VERSION 5.8 ;
BUSBITCHARS "[]" ;
DIVIDERCHAR "/" ;
UNITS
    DATABASE MICRONS 1000 ;
END UNITS

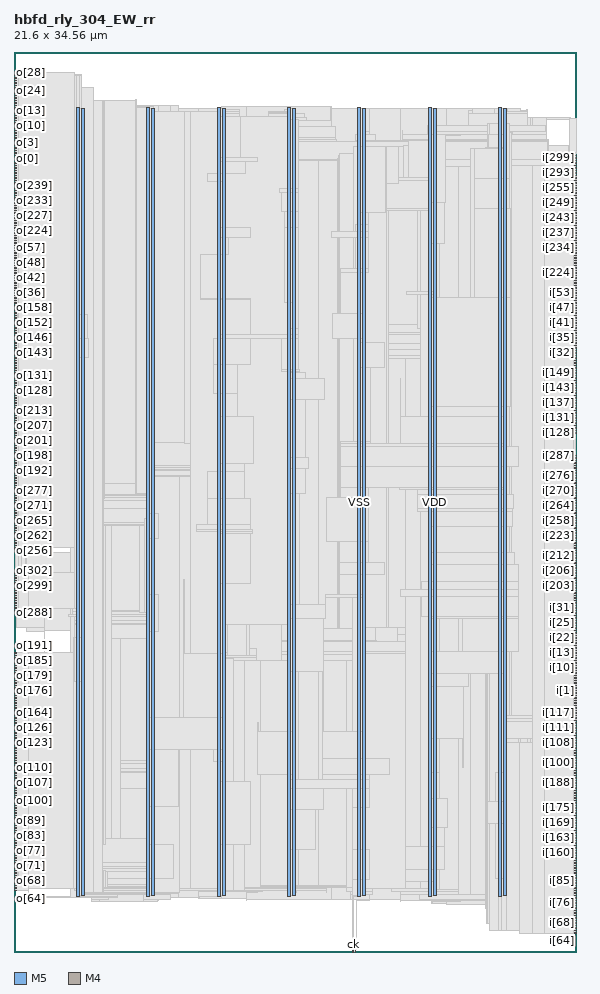
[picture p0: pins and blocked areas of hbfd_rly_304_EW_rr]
MACRO hbfd_rly_304_EW_rr
  FOREIGN hbfd_rly_304_EW_rr 0 0 ;
  CLASS BLOCK ;
  SIZE 21.6 BY 34.56 ;
  PIN ck
    DIRECTION INPUT ;
    USE SIGNAL ;
    PORT
      LAYER M5 ;
        RECT  13.008 0 13.032 0.084 ;
    END
  END ck
  PIN i[0]
    DIRECTION INPUT ;
    USE SIGNAL ;
    PORT
      LAYER M4 ;
        RECT  21.516 9.936 21.6 9.96 ;
    END
  END i[0]
  PIN i[100]
    DIRECTION INPUT ;
    USE SIGNAL ;
    PORT
      LAYER M4 ;
        RECT  21.516 7.248 21.6 7.272 ;
    END
  END i[100]
  PIN i[101]
    DIRECTION INPUT ;
    USE SIGNAL ;
    PORT
      LAYER M4 ;
        RECT  21.516 7.344 21.6 7.368 ;
    END
  END i[101]
  PIN i[102]
    DIRECTION INPUT ;
    USE SIGNAL ;
    PORT
      LAYER M4 ;
        RECT  21.516 7.44 21.6 7.464 ;
    END
  END i[102]
  PIN i[103]
    DIRECTION INPUT ;
    USE SIGNAL ;
    PORT
      LAYER M4 ;
        RECT  21.516 7.536 21.6 7.56 ;
    END
  END i[103]
  PIN i[104]
    DIRECTION INPUT ;
    USE SIGNAL ;
    PORT
      LAYER M4 ;
        RECT  21.516 7.632 21.6 7.656 ;
    END
  END i[104]
  PIN i[105]
    DIRECTION INPUT ;
    USE SIGNAL ;
    PORT
      LAYER M4 ;
        RECT  21.516 7.728 21.6 7.752 ;
    END
  END i[105]
  PIN i[106]
    DIRECTION INPUT ;
    USE SIGNAL ;
    PORT
      LAYER M4 ;
        RECT  21.516 7.824 21.6 7.848 ;
    END
  END i[106]
  PIN i[107]
    DIRECTION INPUT ;
    USE SIGNAL ;
    PORT
      LAYER M4 ;
        RECT  21.516 7.92 21.6 7.944 ;
    END
  END i[107]
  PIN i[108]
    DIRECTION INPUT ;
    USE SIGNAL ;
    PORT
      LAYER M4 ;
        RECT  21.516 8.016 21.6 8.04 ;
    END
  END i[108]
  PIN i[109]
    DIRECTION INPUT ;
    USE SIGNAL ;
    PORT
      LAYER M4 ;
        RECT  21.516 8.112 21.6 8.136 ;
    END
  END i[109]
  PIN i[10]
    DIRECTION INPUT ;
    USE SIGNAL ;
    PORT
      LAYER M4 ;
        RECT  21.516 10.896 21.6 10.92 ;
    END
  END i[10]
  PIN i[110]
    DIRECTION INPUT ;
    USE SIGNAL ;
    PORT
      LAYER M4 ;
        RECT  21.516 8.208 21.6 8.232 ;
    END
  END i[110]
  PIN i[111]
    DIRECTION INPUT ;
    USE SIGNAL ;
    PORT
      LAYER M4 ;
        RECT  21.516 8.304 21.6 8.328 ;
    END
  END i[111]
  PIN i[112]
    DIRECTION INPUT ;
    USE SIGNAL ;
    PORT
      LAYER M4 ;
        RECT  21.516 8.4 21.6 8.424 ;
    END
  END i[112]
  PIN i[113]
    DIRECTION INPUT ;
    USE SIGNAL ;
    PORT
      LAYER M4 ;
        RECT  21.516 8.496 21.6 8.52 ;
    END
  END i[113]
  PIN i[114]
    DIRECTION INPUT ;
    USE SIGNAL ;
    PORT
      LAYER M4 ;
        RECT  21.516 8.592 21.6 8.616 ;
    END
  END i[114]
  PIN i[115]
    DIRECTION INPUT ;
    USE SIGNAL ;
    PORT
      LAYER M4 ;
        RECT  21.516 8.688 21.6 8.712 ;
    END
  END i[115]
  PIN i[116]
    DIRECTION INPUT ;
    USE SIGNAL ;
    PORT
      LAYER M4 ;
        RECT  21.516 8.784 21.6 8.808 ;
    END
  END i[116]
  PIN i[117]
    DIRECTION INPUT ;
    USE SIGNAL ;
    PORT
      LAYER M4 ;
        RECT  21.516 8.88 21.6 8.904 ;
    END
  END i[117]
  PIN i[118]
    DIRECTION INPUT ;
    USE SIGNAL ;
    PORT
      LAYER M4 ;
        RECT  21.516 8.976 21.6 9 ;
    END
  END i[118]
  PIN i[119]
    DIRECTION INPUT ;
    USE SIGNAL ;
    PORT
      LAYER M4 ;
        RECT  21.516 9.072 21.6 9.096 ;
    END
  END i[119]
  PIN i[11]
    DIRECTION INPUT ;
    USE SIGNAL ;
    PORT
      LAYER M4 ;
        RECT  21.516 10.992 21.6 11.016 ;
    END
  END i[11]
  PIN i[120]
    DIRECTION INPUT ;
    USE SIGNAL ;
    PORT
      LAYER M4 ;
        RECT  21.516 9.168 21.6 9.192 ;
    END
  END i[120]
  PIN i[121]
    DIRECTION INPUT ;
    USE SIGNAL ;
    PORT
      LAYER M4 ;
        RECT  21.516 9.264 21.6 9.288 ;
    END
  END i[121]
  PIN i[122]
    DIRECTION INPUT ;
    USE SIGNAL ;
    PORT
      LAYER M4 ;
        RECT  21.516 9.36 21.6 9.384 ;
    END
  END i[122]
  PIN i[123]
    DIRECTION INPUT ;
    USE SIGNAL ;
    PORT
      LAYER M4 ;
        RECT  21.516 9.456 21.6 9.48 ;
    END
  END i[123]
  PIN i[124]
    DIRECTION INPUT ;
    USE SIGNAL ;
    PORT
      LAYER M4 ;
        RECT  21.516 9.552 21.6 9.576 ;
    END
  END i[124]
  PIN i[125]
    DIRECTION INPUT ;
    USE SIGNAL ;
    PORT
      LAYER M4 ;
        RECT  21.516 9.648 21.6 9.672 ;
    END
  END i[125]
  PIN i[126]
    DIRECTION INPUT ;
    USE SIGNAL ;
    PORT
      LAYER M4 ;
        RECT  21.516 9.744 21.6 9.768 ;
    END
  END i[126]
  PIN i[127]
    DIRECTION INPUT ;
    USE SIGNAL ;
    PORT
      LAYER M4 ;
        RECT  21.516 9.84 21.6 9.864 ;
    END
  END i[127]
  PIN i[128]
    DIRECTION INPUT ;
    USE SIGNAL ;
    PORT
      LAYER M4 ;
        RECT  21.516 19.92 21.6 19.944 ;
    END
  END i[128]
  PIN i[129]
    DIRECTION INPUT ;
    USE SIGNAL ;
    PORT
      LAYER M4 ;
        RECT  21.516 20.016 21.6 20.04 ;
    END
  END i[129]
  PIN i[12]
    DIRECTION INPUT ;
    USE SIGNAL ;
    PORT
      LAYER M4 ;
        RECT  21.516 11.088 21.6 11.112 ;
    END
  END i[12]
  PIN i[130]
    DIRECTION INPUT ;
    USE SIGNAL ;
    PORT
      LAYER M4 ;
        RECT  21.516 20.112 21.6 20.136 ;
    END
  END i[130]
  PIN i[131]
    DIRECTION INPUT ;
    USE SIGNAL ;
    PORT
      LAYER M4 ;
        RECT  21.516 20.208 21.6 20.232 ;
    END
  END i[131]
  PIN i[132]
    DIRECTION INPUT ;
    USE SIGNAL ;
    PORT
      LAYER M4 ;
        RECT  21.516 20.304 21.6 20.328 ;
    END
  END i[132]
  PIN i[133]
    DIRECTION INPUT ;
    USE SIGNAL ;
    PORT
      LAYER M4 ;
        RECT  21.516 20.4 21.6 20.424 ;
    END
  END i[133]
  PIN i[134]
    DIRECTION INPUT ;
    USE SIGNAL ;
    PORT
      LAYER M4 ;
        RECT  21.516 20.496 21.6 20.52 ;
    END
  END i[134]
  PIN i[135]
    DIRECTION INPUT ;
    USE SIGNAL ;
    PORT
      LAYER M4 ;
        RECT  21.516 20.592 21.6 20.616 ;
    END
  END i[135]
  PIN i[136]
    DIRECTION INPUT ;
    USE SIGNAL ;
    PORT
      LAYER M4 ;
        RECT  21.516 20.688 21.6 20.712 ;
    END
  END i[136]
  PIN i[137]
    DIRECTION INPUT ;
    USE SIGNAL ;
    PORT
      LAYER M4 ;
        RECT  21.516 20.784 21.6 20.808 ;
    END
  END i[137]
  PIN i[138]
    DIRECTION INPUT ;
    USE SIGNAL ;
    PORT
      LAYER M4 ;
        RECT  21.516 20.88 21.6 20.904 ;
    END
  END i[138]
  PIN i[139]
    DIRECTION INPUT ;
    USE SIGNAL ;
    PORT
      LAYER M4 ;
        RECT  21.516 20.976 21.6 21 ;
    END
  END i[139]
  PIN i[13]
    DIRECTION INPUT ;
    USE SIGNAL ;
    PORT
      LAYER M4 ;
        RECT  21.516 11.184 21.6 11.208 ;
    END
  END i[13]
  PIN i[140]
    DIRECTION INPUT ;
    USE SIGNAL ;
    PORT
      LAYER M4 ;
        RECT  21.516 21.072 21.6 21.096 ;
    END
  END i[140]
  PIN i[141]
    DIRECTION INPUT ;
    USE SIGNAL ;
    PORT
      LAYER M4 ;
        RECT  21.516 21.168 21.6 21.192 ;
    END
  END i[141]
  PIN i[142]
    DIRECTION INPUT ;
    USE SIGNAL ;
    PORT
      LAYER M4 ;
        RECT  21.516 21.264 21.6 21.288 ;
    END
  END i[142]
  PIN i[143]
    DIRECTION INPUT ;
    USE SIGNAL ;
    PORT
      LAYER M4 ;
        RECT  21.516 21.36 21.6 21.384 ;
    END
  END i[143]
  PIN i[144]
    DIRECTION INPUT ;
    USE SIGNAL ;
    PORT
      LAYER M4 ;
        RECT  21.516 21.456 21.6 21.48 ;
    END
  END i[144]
  PIN i[145]
    DIRECTION INPUT ;
    USE SIGNAL ;
    PORT
      LAYER M4 ;
        RECT  21.516 21.552 21.6 21.576 ;
    END
  END i[145]
  PIN i[146]
    DIRECTION INPUT ;
    USE SIGNAL ;
    PORT
      LAYER M4 ;
        RECT  21.516 21.648 21.6 21.672 ;
    END
  END i[146]
  PIN i[147]
    DIRECTION INPUT ;
    USE SIGNAL ;
    PORT
      LAYER M4 ;
        RECT  21.516 21.744 21.6 21.768 ;
    END
  END i[147]
  PIN i[148]
    DIRECTION INPUT ;
    USE SIGNAL ;
    PORT
      LAYER M4 ;
        RECT  21.516 21.84 21.6 21.864 ;
    END
  END i[148]
  PIN i[149]
    DIRECTION INPUT ;
    USE SIGNAL ;
    PORT
      LAYER M4 ;
        RECT  21.516 21.936 21.6 21.96 ;
    END
  END i[149]
  PIN i[14]
    DIRECTION INPUT ;
    USE SIGNAL ;
    PORT
      LAYER M4 ;
        RECT  21.516 11.28 21.6 11.304 ;
    END
  END i[14]
  PIN i[150]
    DIRECTION INPUT ;
    USE SIGNAL ;
    PORT
      LAYER M4 ;
        RECT  21.516 22.032 21.6 22.056 ;
    END
  END i[150]
  PIN i[151]
    DIRECTION INPUT ;
    USE SIGNAL ;
    PORT
      LAYER M4 ;
        RECT  21.516 22.128 21.6 22.152 ;
    END
  END i[151]
  PIN i[152]
    DIRECTION INPUT ;
    USE SIGNAL ;
    PORT
      LAYER M4 ;
        RECT  21.516 22.224 21.6 22.248 ;
    END
  END i[152]
  PIN i[153]
    DIRECTION INPUT ;
    USE SIGNAL ;
    PORT
      LAYER M4 ;
        RECT  21.516 22.32 21.6 22.344 ;
    END
  END i[153]
  PIN i[154]
    DIRECTION INPUT ;
    USE SIGNAL ;
    PORT
      LAYER M4 ;
        RECT  21.516 22.416 21.6 22.44 ;
    END
  END i[154]
  PIN i[155]
    DIRECTION INPUT ;
    USE SIGNAL ;
    PORT
      LAYER M4 ;
        RECT  21.516 22.512 21.6 22.536 ;
    END
  END i[155]
  PIN i[156]
    DIRECTION INPUT ;
    USE SIGNAL ;
    PORT
      LAYER M4 ;
        RECT  21.516 22.608 21.6 22.632 ;
    END
  END i[156]
  PIN i[157]
    DIRECTION INPUT ;
    USE SIGNAL ;
    PORT
      LAYER M4 ;
        RECT  21.516 22.704 21.6 22.728 ;
    END
  END i[157]
  PIN i[158]
    DIRECTION INPUT ;
    USE SIGNAL ;
    PORT
      LAYER M4 ;
        RECT  21.516 22.8 21.6 22.824 ;
    END
  END i[158]
  PIN i[159]
    DIRECTION INPUT ;
    USE SIGNAL ;
    PORT
      LAYER M4 ;
        RECT  21.516 22.896 21.6 22.92 ;
    END
  END i[159]
  PIN i[15]
    DIRECTION INPUT ;
    USE SIGNAL ;
    PORT
      LAYER M4 ;
        RECT  21.516 11.376 21.6 11.4 ;
    END
  END i[15]
  PIN i[160]
    DIRECTION INPUT ;
    USE SIGNAL ;
    PORT
      LAYER M4 ;
        RECT  21.516 3.792 21.6 3.816 ;
    END
  END i[160]
  PIN i[161]
    DIRECTION INPUT ;
    USE SIGNAL ;
    PORT
      LAYER M4 ;
        RECT  21.516 3.888 21.6 3.912 ;
    END
  END i[161]
  PIN i[162]
    DIRECTION INPUT ;
    USE SIGNAL ;
    PORT
      LAYER M4 ;
        RECT  21.516 3.984 21.6 4.008 ;
    END
  END i[162]
  PIN i[163]
    DIRECTION INPUT ;
    USE SIGNAL ;
    PORT
      LAYER M4 ;
        RECT  21.516 4.08 21.6 4.104 ;
    END
  END i[163]
  PIN i[164]
    DIRECTION INPUT ;
    USE SIGNAL ;
    PORT
      LAYER M4 ;
        RECT  21.516 4.176 21.6 4.2 ;
    END
  END i[164]
  PIN i[165]
    DIRECTION INPUT ;
    USE SIGNAL ;
    PORT
      LAYER M4 ;
        RECT  21.516 4.272 21.6 4.296 ;
    END
  END i[165]
  PIN i[166]
    DIRECTION INPUT ;
    USE SIGNAL ;
    PORT
      LAYER M4 ;
        RECT  21.516 4.368 21.6 4.392 ;
    END
  END i[166]
  PIN i[167]
    DIRECTION INPUT ;
    USE SIGNAL ;
    PORT
      LAYER M4 ;
        RECT  21.516 4.464 21.6 4.488 ;
    END
  END i[167]
  PIN i[168]
    DIRECTION INPUT ;
    USE SIGNAL ;
    PORT
      LAYER M4 ;
        RECT  21.516 4.56 21.6 4.584 ;
    END
  END i[168]
  PIN i[169]
    DIRECTION INPUT ;
    USE SIGNAL ;
    PORT
      LAYER M4 ;
        RECT  21.516 4.656 21.6 4.68 ;
    END
  END i[169]
  PIN i[16]
    DIRECTION INPUT ;
    USE SIGNAL ;
    PORT
      LAYER M4 ;
        RECT  21.516 11.472 21.6 11.496 ;
    END
  END i[16]
  PIN i[170]
    DIRECTION INPUT ;
    USE SIGNAL ;
    PORT
      LAYER M4 ;
        RECT  21.516 4.752 21.6 4.776 ;
    END
  END i[170]
  PIN i[171]
    DIRECTION INPUT ;
    USE SIGNAL ;
    PORT
      LAYER M4 ;
        RECT  21.516 4.848 21.6 4.872 ;
    END
  END i[171]
  PIN i[172]
    DIRECTION INPUT ;
    USE SIGNAL ;
    PORT
      LAYER M4 ;
        RECT  21.516 4.944 21.6 4.968 ;
    END
  END i[172]
  PIN i[173]
    DIRECTION INPUT ;
    USE SIGNAL ;
    PORT
      LAYER M4 ;
        RECT  21.516 5.04 21.6 5.064 ;
    END
  END i[173]
  PIN i[174]
    DIRECTION INPUT ;
    USE SIGNAL ;
    PORT
      LAYER M4 ;
        RECT  21.516 5.136 21.6 5.16 ;
    END
  END i[174]
  PIN i[175]
    DIRECTION INPUT ;
    USE SIGNAL ;
    PORT
      LAYER M4 ;
        RECT  21.516 5.232 21.6 5.256 ;
    END
  END i[175]
  PIN i[176]
    DIRECTION INPUT ;
    USE SIGNAL ;
    PORT
      LAYER M4 ;
        RECT  21.516 5.328 21.6 5.352 ;
    END
  END i[176]
  PIN i[177]
    DIRECTION INPUT ;
    USE SIGNAL ;
    PORT
      LAYER M4 ;
        RECT  21.516 5.424 21.6 5.448 ;
    END
  END i[177]
  PIN i[178]
    DIRECTION INPUT ;
    USE SIGNAL ;
    PORT
      LAYER M4 ;
        RECT  21.516 5.52 21.6 5.544 ;
    END
  END i[178]
  PIN i[179]
    DIRECTION INPUT ;
    USE SIGNAL ;
    PORT
      LAYER M4 ;
        RECT  21.516 5.616 21.6 5.64 ;
    END
  END i[179]
  PIN i[17]
    DIRECTION INPUT ;
    USE SIGNAL ;
    PORT
      LAYER M4 ;
        RECT  21.516 11.568 21.6 11.592 ;
    END
  END i[17]
  PIN i[180]
    DIRECTION INPUT ;
    USE SIGNAL ;
    PORT
      LAYER M4 ;
        RECT  21.516 5.712 21.6 5.736 ;
    END
  END i[180]
  PIN i[181]
    DIRECTION INPUT ;
    USE SIGNAL ;
    PORT
      LAYER M4 ;
        RECT  21.516 5.808 21.6 5.832 ;
    END
  END i[181]
  PIN i[182]
    DIRECTION INPUT ;
    USE SIGNAL ;
    PORT
      LAYER M4 ;
        RECT  21.516 5.904 21.6 5.928 ;
    END
  END i[182]
  PIN i[183]
    DIRECTION INPUT ;
    USE SIGNAL ;
    PORT
      LAYER M4 ;
        RECT  21.516 6 21.6 6.024 ;
    END
  END i[183]
  PIN i[184]
    DIRECTION INPUT ;
    USE SIGNAL ;
    PORT
      LAYER M4 ;
        RECT  21.516 6.096 21.6 6.12 ;
    END
  END i[184]
  PIN i[185]
    DIRECTION INPUT ;
    USE SIGNAL ;
    PORT
      LAYER M4 ;
        RECT  21.516 6.192 21.6 6.216 ;
    END
  END i[185]
  PIN i[186]
    DIRECTION INPUT ;
    USE SIGNAL ;
    PORT
      LAYER M4 ;
        RECT  21.516 6.288 21.6 6.312 ;
    END
  END i[186]
  PIN i[187]
    DIRECTION INPUT ;
    USE SIGNAL ;
    PORT
      LAYER M4 ;
        RECT  21.516 6.384 21.6 6.408 ;
    END
  END i[187]
  PIN i[188]
    DIRECTION INPUT ;
    USE SIGNAL ;
    PORT
      LAYER M4 ;
        RECT  21.516 6.48 21.6 6.504 ;
    END
  END i[188]
  PIN i[189]
    DIRECTION INPUT ;
    USE SIGNAL ;
    PORT
      LAYER M4 ;
        RECT  21.516 6.576 21.6 6.6 ;
    END
  END i[189]
  PIN i[18]
    DIRECTION INPUT ;
    USE SIGNAL ;
    PORT
      LAYER M4 ;
        RECT  21.516 11.664 21.6 11.688 ;
    END
  END i[18]
  PIN i[190]
    DIRECTION INPUT ;
    USE SIGNAL ;
    PORT
      LAYER M4 ;
        RECT  21.516 6.672 21.6 6.696 ;
    END
  END i[190]
  PIN i[191]
    DIRECTION INPUT ;
    USE SIGNAL ;
    PORT
      LAYER M4 ;
        RECT  21.516 6.768 21.6 6.792 ;
    END
  END i[191]
  PIN i[192]
    DIRECTION INPUT ;
    USE SIGNAL ;
    PORT
      LAYER M4 ;
        RECT  21.516 13.008 21.6 13.032 ;
    END
  END i[192]
  PIN i[193]
    DIRECTION INPUT ;
    USE SIGNAL ;
    PORT
      LAYER M4 ;
        RECT  21.516 13.104 21.6 13.128 ;
    END
  END i[193]
  PIN i[194]
    DIRECTION INPUT ;
    USE SIGNAL ;
    PORT
      LAYER M4 ;
        RECT  21.516 13.2 21.6 13.224 ;
    END
  END i[194]
  PIN i[195]
    DIRECTION INPUT ;
    USE SIGNAL ;
    PORT
      LAYER M4 ;
        RECT  21.516 13.296 21.6 13.32 ;
    END
  END i[195]
  PIN i[196]
    DIRECTION INPUT ;
    USE SIGNAL ;
    PORT
      LAYER M4 ;
        RECT  21.516 13.392 21.6 13.416 ;
    END
  END i[196]
  PIN i[197]
    DIRECTION INPUT ;
    USE SIGNAL ;
    PORT
      LAYER M4 ;
        RECT  21.516 13.488 21.6 13.512 ;
    END
  END i[197]
  PIN i[198]
    DIRECTION INPUT ;
    USE SIGNAL ;
    PORT
      LAYER M4 ;
        RECT  21.516 13.584 21.6 13.608 ;
    END
  END i[198]
  PIN i[199]
    DIRECTION INPUT ;
    USE SIGNAL ;
    PORT
      LAYER M4 ;
        RECT  21.516 13.68 21.6 13.704 ;
    END
  END i[199]
  PIN i[19]
    DIRECTION INPUT ;
    USE SIGNAL ;
    PORT
      LAYER M4 ;
        RECT  21.516 11.76 21.6 11.784 ;
    END
  END i[19]
  PIN i[1]
    DIRECTION INPUT ;
    USE SIGNAL ;
    PORT
      LAYER M4 ;
        RECT  21.516 10.032 21.6 10.056 ;
    END
  END i[1]
  PIN i[200]
    DIRECTION INPUT ;
    USE SIGNAL ;
    PORT
      LAYER M4 ;
        RECT  21.516 13.776 21.6 13.8 ;
    END
  END i[200]
  PIN i[201]
    DIRECTION INPUT ;
    USE SIGNAL ;
    PORT
      LAYER M4 ;
        RECT  21.516 13.872 21.6 13.896 ;
    END
  END i[201]
  PIN i[202]
    DIRECTION INPUT ;
    USE SIGNAL ;
    PORT
      LAYER M4 ;
        RECT  21.516 13.968 21.6 13.992 ;
    END
  END i[202]
  PIN i[203]
    DIRECTION INPUT ;
    USE SIGNAL ;
    PORT
      LAYER M4 ;
        RECT  21.516 14.064 21.6 14.088 ;
    END
  END i[203]
  PIN i[204]
    DIRECTION INPUT ;
    USE SIGNAL ;
    PORT
      LAYER M4 ;
        RECT  21.516 14.16 21.6 14.184 ;
    END
  END i[204]
  PIN i[205]
    DIRECTION INPUT ;
    USE SIGNAL ;
    PORT
      LAYER M4 ;
        RECT  21.516 14.256 21.6 14.28 ;
    END
  END i[205]
  PIN i[206]
    DIRECTION INPUT ;
    USE SIGNAL ;
    PORT
      LAYER M4 ;
        RECT  21.516 14.352 21.6 14.376 ;
    END
  END i[206]
  PIN i[207]
    DIRECTION INPUT ;
    USE SIGNAL ;
    PORT
      LAYER M4 ;
        RECT  21.516 14.448 21.6 14.472 ;
    END
  END i[207]
  PIN i[208]
    DIRECTION INPUT ;
    USE SIGNAL ;
    PORT
      LAYER M4 ;
        RECT  21.516 14.544 21.6 14.568 ;
    END
  END i[208]
  PIN i[209]
    DIRECTION INPUT ;
    USE SIGNAL ;
    PORT
      LAYER M4 ;
        RECT  21.516 14.64 21.6 14.664 ;
    END
  END i[209]
  PIN i[20]
    DIRECTION INPUT ;
    USE SIGNAL ;
    PORT
      LAYER M4 ;
        RECT  21.516 11.856 21.6 11.88 ;
    END
  END i[20]
  PIN i[210]
    DIRECTION INPUT ;
    USE SIGNAL ;
    PORT
      LAYER M4 ;
        RECT  21.516 14.736 21.6 14.76 ;
    END
  END i[210]
  PIN i[211]
    DIRECTION INPUT ;
    USE SIGNAL ;
    PORT
      LAYER M4 ;
        RECT  21.516 14.832 21.6 14.856 ;
    END
  END i[211]
  PIN i[212]
    DIRECTION INPUT ;
    USE SIGNAL ;
    PORT
      LAYER M4 ;
        RECT  21.516 14.928 21.6 14.952 ;
    END
  END i[212]
  PIN i[213]
    DIRECTION INPUT ;
    USE SIGNAL ;
    PORT
      LAYER M4 ;
        RECT  21.516 15.024 21.6 15.048 ;
    END
  END i[213]
  PIN i[214]
    DIRECTION INPUT ;
    USE SIGNAL ;
    PORT
      LAYER M4 ;
        RECT  21.516 15.12 21.6 15.144 ;
    END
  END i[214]
  PIN i[215]
    DIRECTION INPUT ;
    USE SIGNAL ;
    PORT
      LAYER M4 ;
        RECT  21.516 15.216 21.6 15.24 ;
    END
  END i[215]
  PIN i[216]
    DIRECTION INPUT ;
    USE SIGNAL ;
    PORT
      LAYER M4 ;
        RECT  21.516 15.312 21.6 15.336 ;
    END
  END i[216]
  PIN i[217]
    DIRECTION INPUT ;
    USE SIGNAL ;
    PORT
      LAYER M4 ;
        RECT  21.516 15.408 21.6 15.432 ;
    END
  END i[217]
  PIN i[218]
    DIRECTION INPUT ;
    USE SIGNAL ;
    PORT
      LAYER M4 ;
        RECT  21.516 15.504 21.6 15.528 ;
    END
  END i[218]
  PIN i[219]
    DIRECTION INPUT ;
    USE SIGNAL ;
    PORT
      LAYER M4 ;
        RECT  21.516 15.6 21.6 15.624 ;
    END
  END i[219]
  PIN i[21]
    DIRECTION INPUT ;
    USE SIGNAL ;
    PORT
      LAYER M4 ;
        RECT  21.516 11.952 21.6 11.976 ;
    END
  END i[21]
  PIN i[220]
    DIRECTION INPUT ;
    USE SIGNAL ;
    PORT
      LAYER M4 ;
        RECT  21.516 15.696 21.6 15.72 ;
    END
  END i[220]
  PIN i[221]
    DIRECTION INPUT ;
    USE SIGNAL ;
    PORT
      LAYER M4 ;
        RECT  21.516 15.792 21.6 15.816 ;
    END
  END i[221]
  PIN i[222]
    DIRECTION INPUT ;
    USE SIGNAL ;
    PORT
      LAYER M4 ;
        RECT  21.516 15.888 21.6 15.912 ;
    END
  END i[222]
  PIN i[223]
    DIRECTION INPUT ;
    USE SIGNAL ;
    PORT
      LAYER M4 ;
        RECT  21.516 15.984 21.6 16.008 ;
    END
  END i[223]
  PIN i[224]
    DIRECTION INPUT ;
    USE SIGNAL ;
    PORT
      LAYER M4 ;
        RECT  21.516 26.064 21.6 26.088 ;
    END
  END i[224]
  PIN i[225]
    DIRECTION INPUT ;
    USE SIGNAL ;
    PORT
      LAYER M4 ;
        RECT  21.516 26.16 21.6 26.184 ;
    END
  END i[225]
  PIN i[226]
    DIRECTION INPUT ;
    USE SIGNAL ;
    PORT
      LAYER M4 ;
        RECT  21.516 26.256 21.6 26.28 ;
    END
  END i[226]
  PIN i[227]
    DIRECTION INPUT ;
    USE SIGNAL ;
    PORT
      LAYER M4 ;
        RECT  21.516 26.352 21.6 26.376 ;
    END
  END i[227]
  PIN i[228]
    DIRECTION INPUT ;
    USE SIGNAL ;
    PORT
      LAYER M4 ;
        RECT  21.516 26.448 21.6 26.472 ;
    END
  END i[228]
  PIN i[229]
    DIRECTION INPUT ;
    USE SIGNAL ;
    PORT
      LAYER M4 ;
        RECT  21.516 26.544 21.6 26.568 ;
    END
  END i[229]
  PIN i[22]
    DIRECTION INPUT ;
    USE SIGNAL ;
    PORT
      LAYER M4 ;
        RECT  21.516 12.048 21.6 12.072 ;
    END
  END i[22]
  PIN i[230]
    DIRECTION INPUT ;
    USE SIGNAL ;
    PORT
      LAYER M4 ;
        RECT  21.516 26.64 21.6 26.664 ;
    END
  END i[230]
  PIN i[231]
    DIRECTION INPUT ;
    USE SIGNAL ;
    PORT
      LAYER M4 ;
        RECT  21.516 26.736 21.6 26.76 ;
    END
  END i[231]
  PIN i[232]
    DIRECTION INPUT ;
    USE SIGNAL ;
    PORT
      LAYER M4 ;
        RECT  21.516 26.832 21.6 26.856 ;
    END
  END i[232]
  PIN i[233]
    DIRECTION INPUT ;
    USE SIGNAL ;
    PORT
      LAYER M4 ;
        RECT  21.516 26.928 21.6 26.952 ;
    END
  END i[233]
  PIN i[234]
    DIRECTION INPUT ;
    USE SIGNAL ;
    PORT
      LAYER M4 ;
        RECT  21.516 27.024 21.6 27.048 ;
    END
  END i[234]
  PIN i[235]
    DIRECTION INPUT ;
    USE SIGNAL ;
    PORT
      LAYER M4 ;
        RECT  21.516 27.12 21.6 27.144 ;
    END
  END i[235]
  PIN i[236]
    DIRECTION INPUT ;
    USE SIGNAL ;
    PORT
      LAYER M4 ;
        RECT  21.516 27.216 21.6 27.24 ;
    END
  END i[236]
  PIN i[237]
    DIRECTION INPUT ;
    USE SIGNAL ;
    PORT
      LAYER M4 ;
        RECT  21.516 27.312 21.6 27.336 ;
    END
  END i[237]
  PIN i[238]
    DIRECTION INPUT ;
    USE SIGNAL ;
    PORT
      LAYER M4 ;
        RECT  21.516 27.408 21.6 27.432 ;
    END
  END i[238]
  PIN i[239]
    DIRECTION INPUT ;
    USE SIGNAL ;
    PORT
      LAYER M4 ;
        RECT  21.516 27.504 21.6 27.528 ;
    END
  END i[239]
  PIN i[23]
    DIRECTION INPUT ;
    USE SIGNAL ;
    PORT
      LAYER M4 ;
        RECT  21.516 12.144 21.6 12.168 ;
    END
  END i[23]
  PIN i[240]
    DIRECTION INPUT ;
    USE SIGNAL ;
    PORT
      LAYER M4 ;
        RECT  21.516 27.6 21.6 27.624 ;
    END
  END i[240]
  PIN i[241]
    DIRECTION INPUT ;
    USE SIGNAL ;
    PORT
      LAYER M4 ;
        RECT  21.516 27.696 21.6 27.72 ;
    END
  END i[241]
  PIN i[242]
    DIRECTION INPUT ;
    USE SIGNAL ;
    PORT
      LAYER M4 ;
        RECT  21.516 27.792 21.6 27.816 ;
    END
  END i[242]
  PIN i[243]
    DIRECTION INPUT ;
    USE SIGNAL ;
    PORT
      LAYER M4 ;
        RECT  21.516 27.888 21.6 27.912 ;
    END
  END i[243]
  PIN i[244]
    DIRECTION INPUT ;
    USE SIGNAL ;
    PORT
      LAYER M4 ;
        RECT  21.516 27.984 21.6 28.008 ;
    END
  END i[244]
  PIN i[245]
    DIRECTION INPUT ;
    USE SIGNAL ;
    PORT
      LAYER M4 ;
        RECT  21.516 28.08 21.6 28.104 ;
    END
  END i[245]
  PIN i[246]
    DIRECTION INPUT ;
    USE SIGNAL ;
    PORT
      LAYER M4 ;
        RECT  21.516 28.176 21.6 28.2 ;
    END
  END i[246]
  PIN i[247]
    DIRECTION INPUT ;
    USE SIGNAL ;
    PORT
      LAYER M4 ;
        RECT  21.516 28.272 21.6 28.296 ;
    END
  END i[247]
  PIN i[248]
    DIRECTION INPUT ;
    USE SIGNAL ;
    PORT
      LAYER M4 ;
        RECT  21.516 28.368 21.6 28.392 ;
    END
  END i[248]
  PIN i[249]
    DIRECTION INPUT ;
    USE SIGNAL ;
    PORT
      LAYER M4 ;
        RECT  21.516 28.464 21.6 28.488 ;
    END
  END i[249]
  PIN i[24]
    DIRECTION INPUT ;
    USE SIGNAL ;
    PORT
      LAYER M4 ;
        RECT  21.516 12.24 21.6 12.264 ;
    END
  END i[24]
  PIN i[250]
    DIRECTION INPUT ;
    USE SIGNAL ;
    PORT
      LAYER M4 ;
        RECT  21.516 28.56 21.6 28.584 ;
    END
  END i[250]
  PIN i[251]
    DIRECTION INPUT ;
    USE SIGNAL ;
    PORT
      LAYER M4 ;
        RECT  21.516 28.656 21.6 28.68 ;
    END
  END i[251]
  PIN i[252]
    DIRECTION INPUT ;
    USE SIGNAL ;
    PORT
      LAYER M4 ;
        RECT  21.516 28.752 21.6 28.776 ;
    END
  END i[252]
  PIN i[253]
    DIRECTION INPUT ;
    USE SIGNAL ;
    PORT
      LAYER M4 ;
        RECT  21.516 28.848 21.6 28.872 ;
    END
  END i[253]
  PIN i[254]
    DIRECTION INPUT ;
    USE SIGNAL ;
    PORT
      LAYER M4 ;
        RECT  21.516 28.944 21.6 28.968 ;
    END
  END i[254]
  PIN i[255]
    DIRECTION INPUT ;
    USE SIGNAL ;
    PORT
      LAYER M4 ;
        RECT  21.516 29.04 21.6 29.064 ;
    END
  END i[255]
  PIN i[256]
    DIRECTION INPUT ;
    USE SIGNAL ;
    PORT
      LAYER M4 ;
        RECT  21.516 16.08 21.6 16.104 ;
    END
  END i[256]
  PIN i[257]
    DIRECTION INPUT ;
    USE SIGNAL ;
    PORT
      LAYER M4 ;
        RECT  21.516 16.176 21.6 16.2 ;
    END
  END i[257]
  PIN i[258]
    DIRECTION INPUT ;
    USE SIGNAL ;
    PORT
      LAYER M4 ;
        RECT  21.516 16.272 21.6 16.296 ;
    END
  END i[258]
  PIN i[259]
    DIRECTION INPUT ;
    USE SIGNAL ;
    PORT
      LAYER M4 ;
        RECT  21.516 16.368 21.6 16.392 ;
    END
  END i[259]
  PIN i[25]
    DIRECTION INPUT ;
    USE SIGNAL ;
    PORT
      LAYER M4 ;
        RECT  21.516 12.336 21.6 12.36 ;
    END
  END i[25]
  PIN i[260]
    DIRECTION INPUT ;
    USE SIGNAL ;
    PORT
      LAYER M4 ;
        RECT  21.516 16.464 21.6 16.488 ;
    END
  END i[260]
  PIN i[261]
    DIRECTION INPUT ;
    USE SIGNAL ;
    PORT
      LAYER M4 ;
        RECT  21.516 16.56 21.6 16.584 ;
    END
  END i[261]
  PIN i[262]
    DIRECTION INPUT ;
    USE SIGNAL ;
    PORT
      LAYER M4 ;
        RECT  21.516 16.656 21.6 16.68 ;
    END
  END i[262]
  PIN i[263]
    DIRECTION INPUT ;
    USE SIGNAL ;
    PORT
      LAYER M4 ;
        RECT  21.516 16.752 21.6 16.776 ;
    END
  END i[263]
  PIN i[264]
    DIRECTION INPUT ;
    USE SIGNAL ;
    PORT
      LAYER M4 ;
        RECT  21.516 16.848 21.6 16.872 ;
    END
  END i[264]
  PIN i[265]
    DIRECTION INPUT ;
    USE SIGNAL ;
    PORT
      LAYER M4 ;
        RECT  21.516 16.944 21.6 16.968 ;
    END
  END i[265]
  PIN i[266]
    DIRECTION INPUT ;
    USE SIGNAL ;
    PORT
      LAYER M4 ;
        RECT  21.516 17.04 21.6 17.064 ;
    END
  END i[266]
  PIN i[267]
    DIRECTION INPUT ;
    USE SIGNAL ;
    PORT
      LAYER M4 ;
        RECT  21.516 17.136 21.6 17.16 ;
    END
  END i[267]
  PIN i[268]
    DIRECTION INPUT ;
    USE SIGNAL ;
    PORT
      LAYER M4 ;
        RECT  21.516 17.232 21.6 17.256 ;
    END
  END i[268]
  PIN i[269]
    DIRECTION INPUT ;
    USE SIGNAL ;
    PORT
      LAYER M4 ;
        RECT  21.516 17.328 21.6 17.352 ;
    END
  END i[269]
  PIN i[26]
    DIRECTION INPUT ;
    USE SIGNAL ;
    PORT
      LAYER M4 ;
        RECT  21.516 12.432 21.6 12.456 ;
    END
  END i[26]
  PIN i[270]
    DIRECTION INPUT ;
    USE SIGNAL ;
    PORT
      LAYER M4 ;
        RECT  21.516 17.424 21.6 17.448 ;
    END
  END i[270]
  PIN i[271]
    DIRECTION INPUT ;
    USE SIGNAL ;
    PORT
      LAYER M4 ;
        RECT  21.516 17.52 21.6 17.544 ;
    END
  END i[271]
  PIN i[272]
    DIRECTION INPUT ;
    USE SIGNAL ;
    PORT
      LAYER M4 ;
        RECT  21.516 17.616 21.6 17.64 ;
    END
  END i[272]
  PIN i[273]
    DIRECTION INPUT ;
    USE SIGNAL ;
    PORT
      LAYER M4 ;
        RECT  21.516 17.712 21.6 17.736 ;
    END
  END i[273]
  PIN i[274]
    DIRECTION INPUT ;
    USE SIGNAL ;
    PORT
      LAYER M4 ;
        RECT  21.516 17.808 21.6 17.832 ;
    END
  END i[274]
  PIN i[275]
    DIRECTION INPUT ;
    USE SIGNAL ;
    PORT
      LAYER M4 ;
        RECT  21.516 17.904 21.6 17.928 ;
    END
  END i[275]
  PIN i[276]
    DIRECTION INPUT ;
    USE SIGNAL ;
    PORT
      LAYER M4 ;
        RECT  21.516 18 21.6 18.024 ;
    END
  END i[276]
  PIN i[277]
    DIRECTION INPUT ;
    USE SIGNAL ;
    PORT
      LAYER M4 ;
        RECT  21.516 18.096 21.6 18.12 ;
    END
  END i[277]
  PIN i[278]
    DIRECTION INPUT ;
    USE SIGNAL ;
    PORT
      LAYER M4 ;
        RECT  21.516 18.192 21.6 18.216 ;
    END
  END i[278]
  PIN i[279]
    DIRECTION INPUT ;
    USE SIGNAL ;
    PORT
      LAYER M4 ;
        RECT  21.516 18.288 21.6 18.312 ;
    END
  END i[279]
  PIN i[27]
    DIRECTION INPUT ;
    USE SIGNAL ;
    PORT
      LAYER M4 ;
        RECT  21.516 12.528 21.6 12.552 ;
    END
  END i[27]
  PIN i[280]
    DIRECTION INPUT ;
    USE SIGNAL ;
    PORT
      LAYER M4 ;
        RECT  21.516 18.384 21.6 18.408 ;
    END
  END i[280]
  PIN i[281]
    DIRECTION INPUT ;
    USE SIGNAL ;
    PORT
      LAYER M4 ;
        RECT  21.516 18.48 21.6 18.504 ;
    END
  END i[281]
  PIN i[282]
    DIRECTION INPUT ;
    USE SIGNAL ;
    PORT
      LAYER M4 ;
        RECT  21.516 18.576 21.6 18.6 ;
    END
  END i[282]
  PIN i[283]
    DIRECTION INPUT ;
    USE SIGNAL ;
    PORT
      LAYER M4 ;
        RECT  21.516 18.672 21.6 18.696 ;
    END
  END i[283]
  PIN i[284]
    DIRECTION INPUT ;
    USE SIGNAL ;
    PORT
      LAYER M4 ;
        RECT  21.516 18.768 21.6 18.792 ;
    END
  END i[284]
  PIN i[285]
    DIRECTION INPUT ;
    USE SIGNAL ;
    PORT
      LAYER M4 ;
        RECT  21.516 18.864 21.6 18.888 ;
    END
  END i[285]
  PIN i[286]
    DIRECTION INPUT ;
    USE SIGNAL ;
    PORT
      LAYER M4 ;
        RECT  21.516 18.96 21.6 18.984 ;
    END
  END i[286]
  PIN i[287]
    DIRECTION INPUT ;
    USE SIGNAL ;
    PORT
      LAYER M4 ;
        RECT  21.516 19.056 21.6 19.08 ;
    END
  END i[287]
  PIN i[288]
    DIRECTION INPUT ;
    USE SIGNAL ;
    PORT
      LAYER M4 ;
        RECT  21.516 29.136 21.6 29.16 ;
    END
  END i[288]
  PIN i[289]
    DIRECTION INPUT ;
    USE SIGNAL ;
    PORT
      LAYER M4 ;
        RECT  21.516 29.232 21.6 29.256 ;
    END
  END i[289]
  PIN i[28]
    DIRECTION INPUT ;
    USE SIGNAL ;
    PORT
      LAYER M4 ;
        RECT  21.516 12.624 21.6 12.648 ;
    END
  END i[28]
  PIN i[290]
    DIRECTION INPUT ;
    USE SIGNAL ;
    PORT
      LAYER M4 ;
        RECT  21.516 29.328 21.6 29.352 ;
    END
  END i[290]
  PIN i[291]
    DIRECTION INPUT ;
    USE SIGNAL ;
    PORT
      LAYER M4 ;
        RECT  21.516 29.424 21.6 29.448 ;
    END
  END i[291]
  PIN i[292]
    DIRECTION INPUT ;
    USE SIGNAL ;
    PORT
      LAYER M4 ;
        RECT  21.516 29.52 21.6 29.544 ;
    END
  END i[292]
  PIN i[293]
    DIRECTION INPUT ;
    USE SIGNAL ;
    PORT
      LAYER M4 ;
        RECT  21.516 29.616 21.6 29.64 ;
    END
  END i[293]
  PIN i[294]
    DIRECTION INPUT ;
    USE SIGNAL ;
    PORT
      LAYER M4 ;
        RECT  21.516 29.712 21.6 29.736 ;
    END
  END i[294]
  PIN i[295]
    DIRECTION INPUT ;
    USE SIGNAL ;
    PORT
      LAYER M4 ;
        RECT  21.516 29.808 21.6 29.832 ;
    END
  END i[295]
  PIN i[296]
    DIRECTION INPUT ;
    USE SIGNAL ;
    PORT
      LAYER M4 ;
        RECT  21.516 29.904 21.6 29.928 ;
    END
  END i[296]
  PIN i[297]
    DIRECTION INPUT ;
    USE SIGNAL ;
    PORT
      LAYER M4 ;
        RECT  21.516 30 21.6 30.024 ;
    END
  END i[297]
  PIN i[298]
    DIRECTION INPUT ;
    USE SIGNAL ;
    PORT
      LAYER M4 ;
        RECT  21.516 30.096 21.6 30.12 ;
    END
  END i[298]
  PIN i[299]
    DIRECTION INPUT ;
    USE SIGNAL ;
    PORT
      LAYER M4 ;
        RECT  21.516 30.192 21.6 30.216 ;
    END
  END i[299]
  PIN i[29]
    DIRECTION INPUT ;
    USE SIGNAL ;
    PORT
      LAYER M4 ;
        RECT  21.516 12.72 21.6 12.744 ;
    END
  END i[29]
  PIN i[2]
    DIRECTION INPUT ;
    USE SIGNAL ;
    PORT
      LAYER M4 ;
        RECT  21.516 10.128 21.6 10.152 ;
    END
  END i[2]
  PIN i[300]
    DIRECTION INPUT ;
    USE SIGNAL ;
    PORT
      LAYER M4 ;
        RECT  21.516 30.288 21.6 30.312 ;
    END
  END i[300]
  PIN i[301]
    DIRECTION INPUT ;
    USE SIGNAL ;
    PORT
      LAYER M4 ;
        RECT  21.516 30.384 21.6 30.408 ;
    END
  END i[301]
  PIN i[302]
    DIRECTION INPUT ;
    USE SIGNAL ;
    PORT
      LAYER M4 ;
        RECT  21.516 30.48 21.6 30.504 ;
    END
  END i[302]
  PIN i[303]
    DIRECTION INPUT ;
    USE SIGNAL ;
    PORT
      LAYER M4 ;
        RECT  21.516 30.576 21.6 30.6 ;
    END
  END i[303]
  PIN i[30]
    DIRECTION INPUT ;
    USE SIGNAL ;
    PORT
      LAYER M4 ;
        RECT  21.516 12.816 21.6 12.84 ;
    END
  END i[30]
  PIN i[31]
    DIRECTION INPUT ;
    USE SIGNAL ;
    PORT
      LAYER M4 ;
        RECT  21.516 12.912 21.6 12.936 ;
    END
  END i[31]
  PIN i[32]
    DIRECTION INPUT ;
    USE SIGNAL ;
    PORT
      LAYER M4 ;
        RECT  21.516 22.992 21.6 23.016 ;
    END
  END i[32]
  PIN i[33]
    DIRECTION INPUT ;
    USE SIGNAL ;
    PORT
      LAYER M4 ;
        RECT  21.516 23.088 21.6 23.112 ;
    END
  END i[33]
  PIN i[34]
    DIRECTION INPUT ;
    USE SIGNAL ;
    PORT
      LAYER M4 ;
        RECT  21.516 23.184 21.6 23.208 ;
    END
  END i[34]
  PIN i[35]
    DIRECTION INPUT ;
    USE SIGNAL ;
    PORT
      LAYER M4 ;
        RECT  21.516 23.28 21.6 23.304 ;
    END
  END i[35]
  PIN i[36]
    DIRECTION INPUT ;
    USE SIGNAL ;
    PORT
      LAYER M4 ;
        RECT  21.516 23.376 21.6 23.4 ;
    END
  END i[36]
  PIN i[37]
    DIRECTION INPUT ;
    USE SIGNAL ;
    PORT
      LAYER M4 ;
        RECT  21.516 23.472 21.6 23.496 ;
    END
  END i[37]
  PIN i[38]
    DIRECTION INPUT ;
    USE SIGNAL ;
    PORT
      LAYER M4 ;
        RECT  21.516 23.568 21.6 23.592 ;
    END
  END i[38]
  PIN i[39]
    DIRECTION INPUT ;
    USE SIGNAL ;
    PORT
      LAYER M4 ;
        RECT  21.516 23.664 21.6 23.688 ;
    END
  END i[39]
  PIN i[3]
    DIRECTION INPUT ;
    USE SIGNAL ;
    PORT
      LAYER M4 ;
        RECT  21.516 10.224 21.6 10.248 ;
    END
  END i[3]
  PIN i[40]
    DIRECTION INPUT ;
    USE SIGNAL ;
    PORT
      LAYER M4 ;
        RECT  21.516 23.76 21.6 23.784 ;
    END
  END i[40]
  PIN i[41]
    DIRECTION INPUT ;
    USE SIGNAL ;
    PORT
      LAYER M4 ;
        RECT  21.516 23.856 21.6 23.88 ;
    END
  END i[41]
  PIN i[42]
    DIRECTION INPUT ;
    USE SIGNAL ;
    PORT
      LAYER M4 ;
        RECT  21.516 23.952 21.6 23.976 ;
    END
  END i[42]
  PIN i[43]
    DIRECTION INPUT ;
    USE SIGNAL ;
    PORT
      LAYER M4 ;
        RECT  21.516 24.048 21.6 24.072 ;
    END
  END i[43]
  PIN i[44]
    DIRECTION INPUT ;
    USE SIGNAL ;
    PORT
      LAYER M4 ;
        RECT  21.516 24.144 21.6 24.168 ;
    END
  END i[44]
  PIN i[45]
    DIRECTION INPUT ;
    USE SIGNAL ;
    PORT
      LAYER M4 ;
        RECT  21.516 24.24 21.6 24.264 ;
    END
  END i[45]
  PIN i[46]
    DIRECTION INPUT ;
    USE SIGNAL ;
    PORT
      LAYER M4 ;
        RECT  21.516 24.336 21.6 24.36 ;
    END
  END i[46]
  PIN i[47]
    DIRECTION INPUT ;
    USE SIGNAL ;
    PORT
      LAYER M4 ;
        RECT  21.516 24.432 21.6 24.456 ;
    END
  END i[47]
  PIN i[48]
    DIRECTION INPUT ;
    USE SIGNAL ;
    PORT
      LAYER M4 ;
        RECT  21.516 24.528 21.6 24.552 ;
    END
  END i[48]
  PIN i[49]
    DIRECTION INPUT ;
    USE SIGNAL ;
    PORT
      LAYER M4 ;
        RECT  21.516 24.624 21.6 24.648 ;
    END
  END i[49]
  PIN i[4]
    DIRECTION INPUT ;
    USE SIGNAL ;
    PORT
      LAYER M4 ;
        RECT  21.516 10.32 21.6 10.344 ;
    END
  END i[4]
  PIN i[50]
    DIRECTION INPUT ;
    USE SIGNAL ;
    PORT
      LAYER M4 ;
        RECT  21.516 24.72 21.6 24.744 ;
    END
  END i[50]
  PIN i[51]
    DIRECTION INPUT ;
    USE SIGNAL ;
    PORT
      LAYER M4 ;
        RECT  21.516 24.816 21.6 24.84 ;
    END
  END i[51]
  PIN i[52]
    DIRECTION INPUT ;
    USE SIGNAL ;
    PORT
      LAYER M4 ;
        RECT  21.516 24.912 21.6 24.936 ;
    END
  END i[52]
  PIN i[53]
    DIRECTION INPUT ;
    USE SIGNAL ;
    PORT
      LAYER M4 ;
        RECT  21.516 25.008 21.6 25.032 ;
    END
  END i[53]
  PIN i[54]
    DIRECTION INPUT ;
    USE SIGNAL ;
    PORT
      LAYER M4 ;
        RECT  21.516 25.104 21.6 25.128 ;
    END
  END i[54]
  PIN i[55]
    DIRECTION INPUT ;
    USE SIGNAL ;
    PORT
      LAYER M4 ;
        RECT  21.516 25.2 21.6 25.224 ;
    END
  END i[55]
  PIN i[56]
    DIRECTION INPUT ;
    USE SIGNAL ;
    PORT
      LAYER M4 ;
        RECT  21.516 25.296 21.6 25.32 ;
    END
  END i[56]
  PIN i[57]
    DIRECTION INPUT ;
    USE SIGNAL ;
    PORT
      LAYER M4 ;
        RECT  21.516 25.392 21.6 25.416 ;
    END
  END i[57]
  PIN i[58]
    DIRECTION INPUT ;
    USE SIGNAL ;
    PORT
      LAYER M4 ;
        RECT  21.516 25.488 21.6 25.512 ;
    END
  END i[58]
  PIN i[59]
    DIRECTION INPUT ;
    USE SIGNAL ;
    PORT
      LAYER M4 ;
        RECT  21.516 25.584 21.6 25.608 ;
    END
  END i[59]
  PIN i[5]
    DIRECTION INPUT ;
    USE SIGNAL ;
    PORT
      LAYER M4 ;
        RECT  21.516 10.416 21.6 10.44 ;
    END
  END i[5]
  PIN i[60]
    DIRECTION INPUT ;
    USE SIGNAL ;
    PORT
      LAYER M4 ;
        RECT  21.516 25.68 21.6 25.704 ;
    END
  END i[60]
  PIN i[61]
    DIRECTION INPUT ;
    USE SIGNAL ;
    PORT
      LAYER M4 ;
        RECT  21.516 25.776 21.6 25.8 ;
    END
  END i[61]
  PIN i[62]
    DIRECTION INPUT ;
    USE SIGNAL ;
    PORT
      LAYER M4 ;
        RECT  21.516 25.872 21.6 25.896 ;
    END
  END i[62]
  PIN i[63]
    DIRECTION INPUT ;
    USE SIGNAL ;
    PORT
      LAYER M4 ;
        RECT  21.516 25.968 21.6 25.992 ;
    END
  END i[63]
  PIN i[64]
    DIRECTION INPUT ;
    USE SIGNAL ;
    PORT
      LAYER M4 ;
        RECT  21.516 0.72 21.6 0.744 ;
    END
  END i[64]
  PIN i[65]
    DIRECTION INPUT ;
    USE SIGNAL ;
    PORT
      LAYER M4 ;
        RECT  21.516 0.816 21.6 0.84 ;
    END
  END i[65]
  PIN i[66]
    DIRECTION INPUT ;
    USE SIGNAL ;
    PORT
      LAYER M4 ;
        RECT  21.516 0.912 21.6 0.936 ;
    END
  END i[66]
  PIN i[67]
    DIRECTION INPUT ;
    USE SIGNAL ;
    PORT
      LAYER M4 ;
        RECT  21.516 1.008 21.6 1.032 ;
    END
  END i[67]
  PIN i[68]
    DIRECTION INPUT ;
    USE SIGNAL ;
    PORT
      LAYER M4 ;
        RECT  21.516 1.104 21.6 1.128 ;
    END
  END i[68]
  PIN i[69]
    DIRECTION INPUT ;
    USE SIGNAL ;
    PORT
      LAYER M4 ;
        RECT  21.516 1.2 21.6 1.224 ;
    END
  END i[69]
  PIN i[6]
    DIRECTION INPUT ;
    USE SIGNAL ;
    PORT
      LAYER M4 ;
        RECT  21.516 10.512 21.6 10.536 ;
    END
  END i[6]
  PIN i[70]
    DIRECTION INPUT ;
    USE SIGNAL ;
    PORT
      LAYER M4 ;
        RECT  21.516 1.296 21.6 1.32 ;
    END
  END i[70]
  PIN i[71]
    DIRECTION INPUT ;
    USE SIGNAL ;
    PORT
      LAYER M4 ;
        RECT  21.516 1.392 21.6 1.416 ;
    END
  END i[71]
  PIN i[72]
    DIRECTION INPUT ;
    USE SIGNAL ;
    PORT
      LAYER M4 ;
        RECT  21.516 1.488 21.6 1.512 ;
    END
  END i[72]
  PIN i[73]
    DIRECTION INPUT ;
    USE SIGNAL ;
    PORT
      LAYER M4 ;
        RECT  21.516 1.584 21.6 1.608 ;
    END
  END i[73]
  PIN i[74]
    DIRECTION INPUT ;
    USE SIGNAL ;
    PORT
      LAYER M4 ;
        RECT  21.516 1.68 21.6 1.704 ;
    END
  END i[74]
  PIN i[75]
    DIRECTION INPUT ;
    USE SIGNAL ;
    PORT
      LAYER M4 ;
        RECT  21.516 1.776 21.6 1.8 ;
    END
  END i[75]
  PIN i[76]
    DIRECTION INPUT ;
    USE SIGNAL ;
    PORT
      LAYER M4 ;
        RECT  21.516 1.872 21.6 1.896 ;
    END
  END i[76]
  PIN i[77]
    DIRECTION INPUT ;
    USE SIGNAL ;
    PORT
      LAYER M4 ;
        RECT  21.516 1.968 21.6 1.992 ;
    END
  END i[77]
  PIN i[78]
    DIRECTION INPUT ;
    USE SIGNAL ;
    PORT
      LAYER M4 ;
        RECT  21.516 2.064 21.6 2.088 ;
    END
  END i[78]
  PIN i[79]
    DIRECTION INPUT ;
    USE SIGNAL ;
    PORT
      LAYER M4 ;
        RECT  21.516 2.16 21.6 2.184 ;
    END
  END i[79]
  PIN i[7]
    DIRECTION INPUT ;
    USE SIGNAL ;
    PORT
      LAYER M4 ;
        RECT  21.516 10.608 21.6 10.632 ;
    END
  END i[7]
  PIN i[80]
    DIRECTION INPUT ;
    USE SIGNAL ;
    PORT
      LAYER M4 ;
        RECT  21.516 2.256 21.6 2.28 ;
    END
  END i[80]
  PIN i[81]
    DIRECTION INPUT ;
    USE SIGNAL ;
    PORT
      LAYER M4 ;
        RECT  21.516 2.352 21.6 2.376 ;
    END
  END i[81]
  PIN i[82]
    DIRECTION INPUT ;
    USE SIGNAL ;
    PORT
      LAYER M4 ;
        RECT  21.516 2.448 21.6 2.472 ;
    END
  END i[82]
  PIN i[83]
    DIRECTION INPUT ;
    USE SIGNAL ;
    PORT
      LAYER M4 ;
        RECT  21.516 2.544 21.6 2.568 ;
    END
  END i[83]
  PIN i[84]
    DIRECTION INPUT ;
    USE SIGNAL ;
    PORT
      LAYER M4 ;
        RECT  21.516 2.64 21.6 2.664 ;
    END
  END i[84]
  PIN i[85]
    DIRECTION INPUT ;
    USE SIGNAL ;
    PORT
      LAYER M4 ;
        RECT  21.516 2.736 21.6 2.76 ;
    END
  END i[85]
  PIN i[86]
    DIRECTION INPUT ;
    USE SIGNAL ;
    PORT
      LAYER M4 ;
        RECT  21.516 2.832 21.6 2.856 ;
    END
  END i[86]
  PIN i[87]
    DIRECTION INPUT ;
    USE SIGNAL ;
    PORT
      LAYER M4 ;
        RECT  21.516 2.928 21.6 2.952 ;
    END
  END i[87]
  PIN i[88]
    DIRECTION INPUT ;
    USE SIGNAL ;
    PORT
      LAYER M4 ;
        RECT  21.516 3.024 21.6 3.048 ;
    END
  END i[88]
  PIN i[89]
    DIRECTION INPUT ;
    USE SIGNAL ;
    PORT
      LAYER M4 ;
        RECT  21.516 3.12 21.6 3.144 ;
    END
  END i[89]
  PIN i[8]
    DIRECTION INPUT ;
    USE SIGNAL ;
    PORT
      LAYER M4 ;
        RECT  21.516 10.704 21.6 10.728 ;
    END
  END i[8]
  PIN i[90]
    DIRECTION INPUT ;
    USE SIGNAL ;
    PORT
      LAYER M4 ;
        RECT  21.516 3.216 21.6 3.24 ;
    END
  END i[90]
  PIN i[91]
    DIRECTION INPUT ;
    USE SIGNAL ;
    PORT
      LAYER M4 ;
        RECT  21.516 3.312 21.6 3.336 ;
    END
  END i[91]
  PIN i[92]
    DIRECTION INPUT ;
    USE SIGNAL ;
    PORT
      LAYER M4 ;
        RECT  21.516 3.408 21.6 3.432 ;
    END
  END i[92]
  PIN i[93]
    DIRECTION INPUT ;
    USE SIGNAL ;
    PORT
      LAYER M4 ;
        RECT  21.516 3.504 21.6 3.528 ;
    END
  END i[93]
  PIN i[94]
    DIRECTION INPUT ;
    USE SIGNAL ;
    PORT
      LAYER M4 ;
        RECT  21.516 3.6 21.6 3.624 ;
    END
  END i[94]
  PIN i[95]
    DIRECTION INPUT ;
    USE SIGNAL ;
    PORT
      LAYER M4 ;
        RECT  21.516 3.696 21.6 3.72 ;
    END
  END i[95]
  PIN i[96]
    DIRECTION INPUT ;
    USE SIGNAL ;
    PORT
      LAYER M4 ;
        RECT  21.516 6.864 21.6 6.888 ;
    END
  END i[96]
  PIN i[97]
    DIRECTION INPUT ;
    USE SIGNAL ;
    PORT
      LAYER M4 ;
        RECT  21.516 6.96 21.6 6.984 ;
    END
  END i[97]
  PIN i[98]
    DIRECTION INPUT ;
    USE SIGNAL ;
    PORT
      LAYER M4 ;
        RECT  21.516 7.056 21.6 7.08 ;
    END
  END i[98]
  PIN i[99]
    DIRECTION INPUT ;
    USE SIGNAL ;
    PORT
      LAYER M4 ;
        RECT  21.516 7.152 21.6 7.176 ;
    END
  END i[99]
  PIN i[9]
    DIRECTION INPUT ;
    USE SIGNAL ;
    PORT
      LAYER M4 ;
        RECT  21.516 10.8 21.6 10.824 ;
    END
  END i[9]
  PIN o[0]
    DIRECTION OUTPUT ;
    USE SIGNAL ;
    PORT
      LAYER M4 ;
        RECT  0 30.768 0.084 30.792 ;
    END
  END o[0]
  PIN o[100]
    DIRECTION OUTPUT ;
    USE SIGNAL ;
    PORT
      LAYER M4 ;
        RECT  0 5.808 0.084 5.832 ;
    END
  END o[100]
  PIN o[101]
    DIRECTION OUTPUT ;
    USE SIGNAL ;
    PORT
      LAYER M4 ;
        RECT  0 5.904 0.084 5.928 ;
    END
  END o[101]
  PIN o[102]
    DIRECTION OUTPUT ;
    USE SIGNAL ;
    PORT
      LAYER M4 ;
        RECT  0 6 0.084 6.024 ;
    END
  END o[102]
  PIN o[103]
    DIRECTION OUTPUT ;
    USE SIGNAL ;
    PORT
      LAYER M4 ;
        RECT  0 6.096 0.084 6.12 ;
    END
  END o[103]
  PIN o[104]
    DIRECTION OUTPUT ;
    USE SIGNAL ;
    PORT
      LAYER M4 ;
        RECT  0 6.192 0.084 6.216 ;
    END
  END o[104]
  PIN o[105]
    DIRECTION OUTPUT ;
    USE SIGNAL ;
    PORT
      LAYER M4 ;
        RECT  0 6.288 0.084 6.312 ;
    END
  END o[105]
  PIN o[106]
    DIRECTION OUTPUT ;
    USE SIGNAL ;
    PORT
      LAYER M4 ;
        RECT  0 6.384 0.084 6.408 ;
    END
  END o[106]
  PIN o[107]
    DIRECTION OUTPUT ;
    USE SIGNAL ;
    PORT
      LAYER M4 ;
        RECT  0 6.48 0.084 6.504 ;
    END
  END o[107]
  PIN o[108]
    DIRECTION OUTPUT ;
    USE SIGNAL ;
    PORT
      LAYER M4 ;
        RECT  0 6.576 0.084 6.6 ;
    END
  END o[108]
  PIN o[109]
    DIRECTION OUTPUT ;
    USE SIGNAL ;
    PORT
      LAYER M4 ;
        RECT  0 6.672 0.084 6.696 ;
    END
  END o[109]
  PIN o[10]
    DIRECTION OUTPUT ;
    USE SIGNAL ;
    PORT
      LAYER M4 ;
        RECT  0 31.728 0.084 31.752 ;
    END
  END o[10]
  PIN o[110]
    DIRECTION OUTPUT ;
    USE SIGNAL ;
    PORT
      LAYER M4 ;
        RECT  0 6.768 0.084 6.792 ;
    END
  END o[110]
  PIN o[111]
    DIRECTION OUTPUT ;
    USE SIGNAL ;
    PORT
      LAYER M4 ;
        RECT  0 6.864 0.084 6.888 ;
    END
  END o[111]
  PIN o[112]
    DIRECTION OUTPUT ;
    USE SIGNAL ;
    PORT
      LAYER M4 ;
        RECT  0 6.96 0.084 6.984 ;
    END
  END o[112]
  PIN o[113]
    DIRECTION OUTPUT ;
    USE SIGNAL ;
    PORT
      LAYER M4 ;
        RECT  0 7.056 0.084 7.08 ;
    END
  END o[113]
  PIN o[114]
    DIRECTION OUTPUT ;
    USE SIGNAL ;
    PORT
      LAYER M4 ;
        RECT  0 7.152 0.084 7.176 ;
    END
  END o[114]
  PIN o[115]
    DIRECTION OUTPUT ;
    USE SIGNAL ;
    PORT
      LAYER M4 ;
        RECT  0 7.248 0.084 7.272 ;
    END
  END o[115]
  PIN o[116]
    DIRECTION OUTPUT ;
    USE SIGNAL ;
    PORT
      LAYER M4 ;
        RECT  0 7.344 0.084 7.368 ;
    END
  END o[116]
  PIN o[117]
    DIRECTION OUTPUT ;
    USE SIGNAL ;
    PORT
      LAYER M4 ;
        RECT  0 7.44 0.084 7.464 ;
    END
  END o[117]
  PIN o[118]
    DIRECTION OUTPUT ;
    USE SIGNAL ;
    PORT
      LAYER M4 ;
        RECT  0 7.536 0.084 7.56 ;
    END
  END o[118]
  PIN o[119]
    DIRECTION OUTPUT ;
    USE SIGNAL ;
    PORT
      LAYER M4 ;
        RECT  0 7.632 0.084 7.656 ;
    END
  END o[119]
  PIN o[11]
    DIRECTION OUTPUT ;
    USE SIGNAL ;
    PORT
      LAYER M4 ;
        RECT  0 31.824 0.084 31.848 ;
    END
  END o[11]
  PIN o[120]
    DIRECTION OUTPUT ;
    USE SIGNAL ;
    PORT
      LAYER M4 ;
        RECT  0 7.728 0.084 7.752 ;
    END
  END o[120]
  PIN o[121]
    DIRECTION OUTPUT ;
    USE SIGNAL ;
    PORT
      LAYER M4 ;
        RECT  0 7.824 0.084 7.848 ;
    END
  END o[121]
  PIN o[122]
    DIRECTION OUTPUT ;
    USE SIGNAL ;
    PORT
      LAYER M4 ;
        RECT  0 7.92 0.084 7.944 ;
    END
  END o[122]
  PIN o[123]
    DIRECTION OUTPUT ;
    USE SIGNAL ;
    PORT
      LAYER M4 ;
        RECT  0 8.016 0.084 8.04 ;
    END
  END o[123]
  PIN o[124]
    DIRECTION OUTPUT ;
    USE SIGNAL ;
    PORT
      LAYER M4 ;
        RECT  0 8.112 0.084 8.136 ;
    END
  END o[124]
  PIN o[125]
    DIRECTION OUTPUT ;
    USE SIGNAL ;
    PORT
      LAYER M4 ;
        RECT  0 8.208 0.084 8.232 ;
    END
  END o[125]
  PIN o[126]
    DIRECTION OUTPUT ;
    USE SIGNAL ;
    PORT
      LAYER M4 ;
        RECT  0 8.304 0.084 8.328 ;
    END
  END o[126]
  PIN o[127]
    DIRECTION OUTPUT ;
    USE SIGNAL ;
    PORT
      LAYER M4 ;
        RECT  0 8.4 0.084 8.424 ;
    END
  END o[127]
  PIN o[128]
    DIRECTION OUTPUT ;
    USE SIGNAL ;
    PORT
      LAYER M4 ;
        RECT  0 21.552 0.084 21.576 ;
    END
  END o[128]
  PIN o[129]
    DIRECTION OUTPUT ;
    USE SIGNAL ;
    PORT
      LAYER M4 ;
        RECT  0 21.648 0.084 21.672 ;
    END
  END o[129]
  PIN o[12]
    DIRECTION OUTPUT ;
    USE SIGNAL ;
    PORT
      LAYER M4 ;
        RECT  0 31.92 0.084 31.944 ;
    END
  END o[12]
  PIN o[130]
    DIRECTION OUTPUT ;
    USE SIGNAL ;
    PORT
      LAYER M4 ;
        RECT  0 21.744 0.084 21.768 ;
    END
  END o[130]
  PIN o[131]
    DIRECTION OUTPUT ;
    USE SIGNAL ;
    PORT
      LAYER M4 ;
        RECT  0 21.84 0.084 21.864 ;
    END
  END o[131]
  PIN o[132]
    DIRECTION OUTPUT ;
    USE SIGNAL ;
    PORT
      LAYER M4 ;
        RECT  0 21.936 0.084 21.96 ;
    END
  END o[132]
  PIN o[133]
    DIRECTION OUTPUT ;
    USE SIGNAL ;
    PORT
      LAYER M4 ;
        RECT  0 22.032 0.084 22.056 ;
    END
  END o[133]
  PIN o[134]
    DIRECTION OUTPUT ;
    USE SIGNAL ;
    PORT
      LAYER M4 ;
        RECT  0 22.128 0.084 22.152 ;
    END
  END o[134]
  PIN o[135]
    DIRECTION OUTPUT ;
    USE SIGNAL ;
    PORT
      LAYER M4 ;
        RECT  0 22.224 0.084 22.248 ;
    END
  END o[135]
  PIN o[136]
    DIRECTION OUTPUT ;
    USE SIGNAL ;
    PORT
      LAYER M4 ;
        RECT  0 22.32 0.084 22.344 ;
    END
  END o[136]
  PIN o[137]
    DIRECTION OUTPUT ;
    USE SIGNAL ;
    PORT
      LAYER M4 ;
        RECT  0 22.416 0.084 22.44 ;
    END
  END o[137]
  PIN o[138]
    DIRECTION OUTPUT ;
    USE SIGNAL ;
    PORT
      LAYER M4 ;
        RECT  0 22.512 0.084 22.536 ;
    END
  END o[138]
  PIN o[139]
    DIRECTION OUTPUT ;
    USE SIGNAL ;
    PORT
      LAYER M4 ;
        RECT  0 22.608 0.084 22.632 ;
    END
  END o[139]
  PIN o[13]
    DIRECTION OUTPUT ;
    USE SIGNAL ;
    PORT
      LAYER M4 ;
        RECT  0 32.016 0.084 32.04 ;
    END
  END o[13]
  PIN o[140]
    DIRECTION OUTPUT ;
    USE SIGNAL ;
    PORT
      LAYER M4 ;
        RECT  0 22.704 0.084 22.728 ;
    END
  END o[140]
  PIN o[141]
    DIRECTION OUTPUT ;
    USE SIGNAL ;
    PORT
      LAYER M4 ;
        RECT  0 22.8 0.084 22.824 ;
    END
  END o[141]
  PIN o[142]
    DIRECTION OUTPUT ;
    USE SIGNAL ;
    PORT
      LAYER M4 ;
        RECT  0 22.896 0.084 22.92 ;
    END
  END o[142]
  PIN o[143]
    DIRECTION OUTPUT ;
    USE SIGNAL ;
    PORT
      LAYER M4 ;
        RECT  0 22.992 0.084 23.016 ;
    END
  END o[143]
  PIN o[144]
    DIRECTION OUTPUT ;
    USE SIGNAL ;
    PORT
      LAYER M4 ;
        RECT  0 23.088 0.084 23.112 ;
    END
  END o[144]
  PIN o[145]
    DIRECTION OUTPUT ;
    USE SIGNAL ;
    PORT
      LAYER M4 ;
        RECT  0 23.184 0.084 23.208 ;
    END
  END o[145]
  PIN o[146]
    DIRECTION OUTPUT ;
    USE SIGNAL ;
    PORT
      LAYER M4 ;
        RECT  0 23.28 0.084 23.304 ;
    END
  END o[146]
  PIN o[147]
    DIRECTION OUTPUT ;
    USE SIGNAL ;
    PORT
      LAYER M4 ;
        RECT  0 23.376 0.084 23.4 ;
    END
  END o[147]
  PIN o[148]
    DIRECTION OUTPUT ;
    USE SIGNAL ;
    PORT
      LAYER M4 ;
        RECT  0 23.472 0.084 23.496 ;
    END
  END o[148]
  PIN o[149]
    DIRECTION OUTPUT ;
    USE SIGNAL ;
    PORT
      LAYER M4 ;
        RECT  0 23.568 0.084 23.592 ;
    END
  END o[149]
  PIN o[14]
    DIRECTION OUTPUT ;
    USE SIGNAL ;
    PORT
      LAYER M4 ;
        RECT  0 32.112 0.084 32.136 ;
    END
  END o[14]
  PIN o[150]
    DIRECTION OUTPUT ;
    USE SIGNAL ;
    PORT
      LAYER M4 ;
        RECT  0 23.664 0.084 23.688 ;
    END
  END o[150]
  PIN o[151]
    DIRECTION OUTPUT ;
    USE SIGNAL ;
    PORT
      LAYER M4 ;
        RECT  0 23.76 0.084 23.784 ;
    END
  END o[151]
  PIN o[152]
    DIRECTION OUTPUT ;
    USE SIGNAL ;
    PORT
      LAYER M4 ;
        RECT  0 23.856 0.084 23.88 ;
    END
  END o[152]
  PIN o[153]
    DIRECTION OUTPUT ;
    USE SIGNAL ;
    PORT
      LAYER M4 ;
        RECT  0 23.952 0.084 23.976 ;
    END
  END o[153]
  PIN o[154]
    DIRECTION OUTPUT ;
    USE SIGNAL ;
    PORT
      LAYER M4 ;
        RECT  0 24.048 0.084 24.072 ;
    END
  END o[154]
  PIN o[155]
    DIRECTION OUTPUT ;
    USE SIGNAL ;
    PORT
      LAYER M4 ;
        RECT  0 24.144 0.084 24.168 ;
    END
  END o[155]
  PIN o[156]
    DIRECTION OUTPUT ;
    USE SIGNAL ;
    PORT
      LAYER M4 ;
        RECT  0 24.24 0.084 24.264 ;
    END
  END o[156]
  PIN o[157]
    DIRECTION OUTPUT ;
    USE SIGNAL ;
    PORT
      LAYER M4 ;
        RECT  0 24.336 0.084 24.36 ;
    END
  END o[157]
  PIN o[158]
    DIRECTION OUTPUT ;
    USE SIGNAL ;
    PORT
      LAYER M4 ;
        RECT  0 24.432 0.084 24.456 ;
    END
  END o[158]
  PIN o[159]
    DIRECTION OUTPUT ;
    USE SIGNAL ;
    PORT
      LAYER M4 ;
        RECT  0 24.528 0.084 24.552 ;
    END
  END o[159]
  PIN o[15]
    DIRECTION OUTPUT ;
    USE SIGNAL ;
    PORT
      LAYER M4 ;
        RECT  0 32.208 0.084 32.232 ;
    END
  END o[15]
  PIN o[160]
    DIRECTION OUTPUT ;
    USE SIGNAL ;
    PORT
      LAYER M4 ;
        RECT  0 8.496 0.084 8.52 ;
    END
  END o[160]
  PIN o[161]
    DIRECTION OUTPUT ;
    USE SIGNAL ;
    PORT
      LAYER M4 ;
        RECT  0 8.592 0.084 8.616 ;
    END
  END o[161]
  PIN o[162]
    DIRECTION OUTPUT ;
    USE SIGNAL ;
    PORT
      LAYER M4 ;
        RECT  0 8.688 0.084 8.712 ;
    END
  END o[162]
  PIN o[163]
    DIRECTION OUTPUT ;
    USE SIGNAL ;
    PORT
      LAYER M4 ;
        RECT  0 8.784 0.084 8.808 ;
    END
  END o[163]
  PIN o[164]
    DIRECTION OUTPUT ;
    USE SIGNAL ;
    PORT
      LAYER M4 ;
        RECT  0 8.88 0.084 8.904 ;
    END
  END o[164]
  PIN o[165]
    DIRECTION OUTPUT ;
    USE SIGNAL ;
    PORT
      LAYER M4 ;
        RECT  0 8.976 0.084 9 ;
    END
  END o[165]
  PIN o[166]
    DIRECTION OUTPUT ;
    USE SIGNAL ;
    PORT
      LAYER M4 ;
        RECT  0 9.072 0.084 9.096 ;
    END
  END o[166]
  PIN o[167]
    DIRECTION OUTPUT ;
    USE SIGNAL ;
    PORT
      LAYER M4 ;
        RECT  0 9.168 0.084 9.192 ;
    END
  END o[167]
  PIN o[168]
    DIRECTION OUTPUT ;
    USE SIGNAL ;
    PORT
      LAYER M4 ;
        RECT  0 9.264 0.084 9.288 ;
    END
  END o[168]
  PIN o[169]
    DIRECTION OUTPUT ;
    USE SIGNAL ;
    PORT
      LAYER M4 ;
        RECT  0 9.36 0.084 9.384 ;
    END
  END o[169]
  PIN o[16]
    DIRECTION OUTPUT ;
    USE SIGNAL ;
    PORT
      LAYER M4 ;
        RECT  0 32.304 0.084 32.328 ;
    END
  END o[16]
  PIN o[170]
    DIRECTION OUTPUT ;
    USE SIGNAL ;
    PORT
      LAYER M4 ;
        RECT  0 9.456 0.084 9.48 ;
    END
  END o[170]
  PIN o[171]
    DIRECTION OUTPUT ;
    USE SIGNAL ;
    PORT
      LAYER M4 ;
        RECT  0 9.552 0.084 9.576 ;
    END
  END o[171]
  PIN o[172]
    DIRECTION OUTPUT ;
    USE SIGNAL ;
    PORT
      LAYER M4 ;
        RECT  0 9.648 0.084 9.672 ;
    END
  END o[172]
  PIN o[173]
    DIRECTION OUTPUT ;
    USE SIGNAL ;
    PORT
      LAYER M4 ;
        RECT  0 9.744 0.084 9.768 ;
    END
  END o[173]
  PIN o[174]
    DIRECTION OUTPUT ;
    USE SIGNAL ;
    PORT
      LAYER M4 ;
        RECT  0 9.84 0.084 9.864 ;
    END
  END o[174]
  PIN o[175]
    DIRECTION OUTPUT ;
    USE SIGNAL ;
    PORT
      LAYER M4 ;
        RECT  0 9.936 0.084 9.96 ;
    END
  END o[175]
  PIN o[176]
    DIRECTION OUTPUT ;
    USE SIGNAL ;
    PORT
      LAYER M4 ;
        RECT  0 10.032 0.084 10.056 ;
    END
  END o[176]
  PIN o[177]
    DIRECTION OUTPUT ;
    USE SIGNAL ;
    PORT
      LAYER M4 ;
        RECT  0 10.128 0.084 10.152 ;
    END
  END o[177]
  PIN o[178]
    DIRECTION OUTPUT ;
    USE SIGNAL ;
    PORT
      LAYER M4 ;
        RECT  0 10.224 0.084 10.248 ;
    END
  END o[178]
  PIN o[179]
    DIRECTION OUTPUT ;
    USE SIGNAL ;
    PORT
      LAYER M4 ;
        RECT  0 10.32 0.084 10.344 ;
    END
  END o[179]
  PIN o[17]
    DIRECTION OUTPUT ;
    USE SIGNAL ;
    PORT
      LAYER M4 ;
        RECT  0 32.4 0.084 32.424 ;
    END
  END o[17]
  PIN o[180]
    DIRECTION OUTPUT ;
    USE SIGNAL ;
    PORT
      LAYER M4 ;
        RECT  0 10.416 0.084 10.44 ;
    END
  END o[180]
  PIN o[181]
    DIRECTION OUTPUT ;
    USE SIGNAL ;
    PORT
      LAYER M4 ;
        RECT  0 10.512 0.084 10.536 ;
    END
  END o[181]
  PIN o[182]
    DIRECTION OUTPUT ;
    USE SIGNAL ;
    PORT
      LAYER M4 ;
        RECT  0 10.608 0.084 10.632 ;
    END
  END o[182]
  PIN o[183]
    DIRECTION OUTPUT ;
    USE SIGNAL ;
    PORT
      LAYER M4 ;
        RECT  0 10.704 0.084 10.728 ;
    END
  END o[183]
  PIN o[184]
    DIRECTION OUTPUT ;
    USE SIGNAL ;
    PORT
      LAYER M4 ;
        RECT  0 10.8 0.084 10.824 ;
    END
  END o[184]
  PIN o[185]
    DIRECTION OUTPUT ;
    USE SIGNAL ;
    PORT
      LAYER M4 ;
        RECT  0 10.896 0.084 10.92 ;
    END
  END o[185]
  PIN o[186]
    DIRECTION OUTPUT ;
    USE SIGNAL ;
    PORT
      LAYER M4 ;
        RECT  0 10.992 0.084 11.016 ;
    END
  END o[186]
  PIN o[187]
    DIRECTION OUTPUT ;
    USE SIGNAL ;
    PORT
      LAYER M4 ;
        RECT  0 11.088 0.084 11.112 ;
    END
  END o[187]
  PIN o[188]
    DIRECTION OUTPUT ;
    USE SIGNAL ;
    PORT
      LAYER M4 ;
        RECT  0 11.184 0.084 11.208 ;
    END
  END o[188]
  PIN o[189]
    DIRECTION OUTPUT ;
    USE SIGNAL ;
    PORT
      LAYER M4 ;
        RECT  0 11.28 0.084 11.304 ;
    END
  END o[189]
  PIN o[18]
    DIRECTION OUTPUT ;
    USE SIGNAL ;
    PORT
      LAYER M4 ;
        RECT  0 32.496 0.084 32.52 ;
    END
  END o[18]
  PIN o[190]
    DIRECTION OUTPUT ;
    USE SIGNAL ;
    PORT
      LAYER M4 ;
        RECT  0 11.376 0.084 11.4 ;
    END
  END o[190]
  PIN o[191]
    DIRECTION OUTPUT ;
    USE SIGNAL ;
    PORT
      LAYER M4 ;
        RECT  0 11.472 0.084 11.496 ;
    END
  END o[191]
  PIN o[192]
    DIRECTION OUTPUT ;
    USE SIGNAL ;
    PORT
      LAYER M4 ;
        RECT  0 18.48 0.084 18.504 ;
    END
  END o[192]
  PIN o[193]
    DIRECTION OUTPUT ;
    USE SIGNAL ;
    PORT
      LAYER M4 ;
        RECT  0 18.576 0.084 18.6 ;
    END
  END o[193]
  PIN o[194]
    DIRECTION OUTPUT ;
    USE SIGNAL ;
    PORT
      LAYER M4 ;
        RECT  0 18.672 0.084 18.696 ;
    END
  END o[194]
  PIN o[195]
    DIRECTION OUTPUT ;
    USE SIGNAL ;
    PORT
      LAYER M4 ;
        RECT  0 18.768 0.084 18.792 ;
    END
  END o[195]
  PIN o[196]
    DIRECTION OUTPUT ;
    USE SIGNAL ;
    PORT
      LAYER M4 ;
        RECT  0 18.864 0.084 18.888 ;
    END
  END o[196]
  PIN o[197]
    DIRECTION OUTPUT ;
    USE SIGNAL ;
    PORT
      LAYER M4 ;
        RECT  0 18.96 0.084 18.984 ;
    END
  END o[197]
  PIN o[198]
    DIRECTION OUTPUT ;
    USE SIGNAL ;
    PORT
      LAYER M4 ;
        RECT  0 19.056 0.084 19.08 ;
    END
  END o[198]
  PIN o[199]
    DIRECTION OUTPUT ;
    USE SIGNAL ;
    PORT
      LAYER M4 ;
        RECT  0 19.152 0.084 19.176 ;
    END
  END o[199]
  PIN o[19]
    DIRECTION OUTPUT ;
    USE SIGNAL ;
    PORT
      LAYER M4 ;
        RECT  0 32.592 0.084 32.616 ;
    END
  END o[19]
  PIN o[1]
    DIRECTION OUTPUT ;
    USE SIGNAL ;
    PORT
      LAYER M4 ;
        RECT  0 30.864 0.084 30.888 ;
    END
  END o[1]
  PIN o[200]
    DIRECTION OUTPUT ;
    USE SIGNAL ;
    PORT
      LAYER M4 ;
        RECT  0 19.248 0.084 19.272 ;
    END
  END o[200]
  PIN o[201]
    DIRECTION OUTPUT ;
    USE SIGNAL ;
    PORT
      LAYER M4 ;
        RECT  0 19.344 0.084 19.368 ;
    END
  END o[201]
  PIN o[202]
    DIRECTION OUTPUT ;
    USE SIGNAL ;
    PORT
      LAYER M4 ;
        RECT  0 19.44 0.084 19.464 ;
    END
  END o[202]
  PIN o[203]
    DIRECTION OUTPUT ;
    USE SIGNAL ;
    PORT
      LAYER M4 ;
        RECT  0 19.536 0.084 19.56 ;
    END
  END o[203]
  PIN o[204]
    DIRECTION OUTPUT ;
    USE SIGNAL ;
    PORT
      LAYER M4 ;
        RECT  0 19.632 0.084 19.656 ;
    END
  END o[204]
  PIN o[205]
    DIRECTION OUTPUT ;
    USE SIGNAL ;
    PORT
      LAYER M4 ;
        RECT  0 19.728 0.084 19.752 ;
    END
  END o[205]
  PIN o[206]
    DIRECTION OUTPUT ;
    USE SIGNAL ;
    PORT
      LAYER M4 ;
        RECT  0 19.824 0.084 19.848 ;
    END
  END o[206]
  PIN o[207]
    DIRECTION OUTPUT ;
    USE SIGNAL ;
    PORT
      LAYER M4 ;
        RECT  0 19.92 0.084 19.944 ;
    END
  END o[207]
  PIN o[208]
    DIRECTION OUTPUT ;
    USE SIGNAL ;
    PORT
      LAYER M4 ;
        RECT  0 20.016 0.084 20.04 ;
    END
  END o[208]
  PIN o[209]
    DIRECTION OUTPUT ;
    USE SIGNAL ;
    PORT
      LAYER M4 ;
        RECT  0 20.112 0.084 20.136 ;
    END
  END o[209]
  PIN o[20]
    DIRECTION OUTPUT ;
    USE SIGNAL ;
    PORT
      LAYER M4 ;
        RECT  0 32.688 0.084 32.712 ;
    END
  END o[20]
  PIN o[210]
    DIRECTION OUTPUT ;
    USE SIGNAL ;
    PORT
      LAYER M4 ;
        RECT  0 20.208 0.084 20.232 ;
    END
  END o[210]
  PIN o[211]
    DIRECTION OUTPUT ;
    USE SIGNAL ;
    PORT
      LAYER M4 ;
        RECT  0 20.304 0.084 20.328 ;
    END
  END o[211]
  PIN o[212]
    DIRECTION OUTPUT ;
    USE SIGNAL ;
    PORT
      LAYER M4 ;
        RECT  0 20.4 0.084 20.424 ;
    END
  END o[212]
  PIN o[213]
    DIRECTION OUTPUT ;
    USE SIGNAL ;
    PORT
      LAYER M4 ;
        RECT  0 20.496 0.084 20.52 ;
    END
  END o[213]
  PIN o[214]
    DIRECTION OUTPUT ;
    USE SIGNAL ;
    PORT
      LAYER M4 ;
        RECT  0 20.592 0.084 20.616 ;
    END
  END o[214]
  PIN o[215]
    DIRECTION OUTPUT ;
    USE SIGNAL ;
    PORT
      LAYER M4 ;
        RECT  0 20.688 0.084 20.712 ;
    END
  END o[215]
  PIN o[216]
    DIRECTION OUTPUT ;
    USE SIGNAL ;
    PORT
      LAYER M4 ;
        RECT  0 20.784 0.084 20.808 ;
    END
  END o[216]
  PIN o[217]
    DIRECTION OUTPUT ;
    USE SIGNAL ;
    PORT
      LAYER M4 ;
        RECT  0 20.88 0.084 20.904 ;
    END
  END o[217]
  PIN o[218]
    DIRECTION OUTPUT ;
    USE SIGNAL ;
    PORT
      LAYER M4 ;
        RECT  0 20.976 0.084 21 ;
    END
  END o[218]
  PIN o[219]
    DIRECTION OUTPUT ;
    USE SIGNAL ;
    PORT
      LAYER M4 ;
        RECT  0 21.072 0.084 21.096 ;
    END
  END o[219]
  PIN o[21]
    DIRECTION OUTPUT ;
    USE SIGNAL ;
    PORT
      LAYER M4 ;
        RECT  0 32.784 0.084 32.808 ;
    END
  END o[21]
  PIN o[220]
    DIRECTION OUTPUT ;
    USE SIGNAL ;
    PORT
      LAYER M4 ;
        RECT  0 21.168 0.084 21.192 ;
    END
  END o[220]
  PIN o[221]
    DIRECTION OUTPUT ;
    USE SIGNAL ;
    PORT
      LAYER M4 ;
        RECT  0 21.264 0.084 21.288 ;
    END
  END o[221]
  PIN o[222]
    DIRECTION OUTPUT ;
    USE SIGNAL ;
    PORT
      LAYER M4 ;
        RECT  0 21.36 0.084 21.384 ;
    END
  END o[222]
  PIN o[223]
    DIRECTION OUTPUT ;
    USE SIGNAL ;
    PORT
      LAYER M4 ;
        RECT  0 21.456 0.084 21.48 ;
    END
  END o[223]
  PIN o[224]
    DIRECTION OUTPUT ;
    USE SIGNAL ;
    PORT
      LAYER M4 ;
        RECT  0 27.696 0.084 27.72 ;
    END
  END o[224]
  PIN o[225]
    DIRECTION OUTPUT ;
    USE SIGNAL ;
    PORT
      LAYER M4 ;
        RECT  0 27.792 0.084 27.816 ;
    END
  END o[225]
  PIN o[226]
    DIRECTION OUTPUT ;
    USE SIGNAL ;
    PORT
      LAYER M4 ;
        RECT  0 27.888 0.084 27.912 ;
    END
  END o[226]
  PIN o[227]
    DIRECTION OUTPUT ;
    USE SIGNAL ;
    PORT
      LAYER M4 ;
        RECT  0 27.984 0.084 28.008 ;
    END
  END o[227]
  PIN o[228]
    DIRECTION OUTPUT ;
    USE SIGNAL ;
    PORT
      LAYER M4 ;
        RECT  0 28.08 0.084 28.104 ;
    END
  END o[228]
  PIN o[229]
    DIRECTION OUTPUT ;
    USE SIGNAL ;
    PORT
      LAYER M4 ;
        RECT  0 28.176 0.084 28.2 ;
    END
  END o[229]
  PIN o[22]
    DIRECTION OUTPUT ;
    USE SIGNAL ;
    PORT
      LAYER M4 ;
        RECT  0 32.88 0.084 32.904 ;
    END
  END o[22]
  PIN o[230]
    DIRECTION OUTPUT ;
    USE SIGNAL ;
    PORT
      LAYER M4 ;
        RECT  0 28.272 0.084 28.296 ;
    END
  END o[230]
  PIN o[231]
    DIRECTION OUTPUT ;
    USE SIGNAL ;
    PORT
      LAYER M4 ;
        RECT  0 28.368 0.084 28.392 ;
    END
  END o[231]
  PIN o[232]
    DIRECTION OUTPUT ;
    USE SIGNAL ;
    PORT
      LAYER M4 ;
        RECT  0 28.464 0.084 28.488 ;
    END
  END o[232]
  PIN o[233]
    DIRECTION OUTPUT ;
    USE SIGNAL ;
    PORT
      LAYER M4 ;
        RECT  0 28.56 0.084 28.584 ;
    END
  END o[233]
  PIN o[234]
    DIRECTION OUTPUT ;
    USE SIGNAL ;
    PORT
      LAYER M4 ;
        RECT  0 28.656 0.084 28.68 ;
    END
  END o[234]
  PIN o[235]
    DIRECTION OUTPUT ;
    USE SIGNAL ;
    PORT
      LAYER M4 ;
        RECT  0 28.752 0.084 28.776 ;
    END
  END o[235]
  PIN o[236]
    DIRECTION OUTPUT ;
    USE SIGNAL ;
    PORT
      LAYER M4 ;
        RECT  0 28.848 0.084 28.872 ;
    END
  END o[236]
  PIN o[237]
    DIRECTION OUTPUT ;
    USE SIGNAL ;
    PORT
      LAYER M4 ;
        RECT  0 28.944 0.084 28.968 ;
    END
  END o[237]
  PIN o[238]
    DIRECTION OUTPUT ;
    USE SIGNAL ;
    PORT
      LAYER M4 ;
        RECT  0 29.04 0.084 29.064 ;
    END
  END o[238]
  PIN o[239]
    DIRECTION OUTPUT ;
    USE SIGNAL ;
    PORT
      LAYER M4 ;
        RECT  0 29.136 0.084 29.16 ;
    END
  END o[239]
  PIN o[23]
    DIRECTION OUTPUT ;
    USE SIGNAL ;
    PORT
      LAYER M4 ;
        RECT  0 32.976 0.084 33 ;
    END
  END o[23]
  PIN o[240]
    DIRECTION OUTPUT ;
    USE SIGNAL ;
    PORT
      LAYER M4 ;
        RECT  0 29.232 0.084 29.256 ;
    END
  END o[240]
  PIN o[241]
    DIRECTION OUTPUT ;
    USE SIGNAL ;
    PORT
      LAYER M4 ;
        RECT  0 29.328 0.084 29.352 ;
    END
  END o[241]
  PIN o[242]
    DIRECTION OUTPUT ;
    USE SIGNAL ;
    PORT
      LAYER M4 ;
        RECT  0 29.424 0.084 29.448 ;
    END
  END o[242]
  PIN o[243]
    DIRECTION OUTPUT ;
    USE SIGNAL ;
    PORT
      LAYER M4 ;
        RECT  0 29.52 0.084 29.544 ;
    END
  END o[243]
  PIN o[244]
    DIRECTION OUTPUT ;
    USE SIGNAL ;
    PORT
      LAYER M4 ;
        RECT  0 29.616 0.084 29.64 ;
    END
  END o[244]
  PIN o[245]
    DIRECTION OUTPUT ;
    USE SIGNAL ;
    PORT
      LAYER M4 ;
        RECT  0 29.712 0.084 29.736 ;
    END
  END o[245]
  PIN o[246]
    DIRECTION OUTPUT ;
    USE SIGNAL ;
    PORT
      LAYER M4 ;
        RECT  0 29.808 0.084 29.832 ;
    END
  END o[246]
  PIN o[247]
    DIRECTION OUTPUT ;
    USE SIGNAL ;
    PORT
      LAYER M4 ;
        RECT  0 29.904 0.084 29.928 ;
    END
  END o[247]
  PIN o[248]
    DIRECTION OUTPUT ;
    USE SIGNAL ;
    PORT
      LAYER M4 ;
        RECT  0 30 0.084 30.024 ;
    END
  END o[248]
  PIN o[249]
    DIRECTION OUTPUT ;
    USE SIGNAL ;
    PORT
      LAYER M4 ;
        RECT  0 30.096 0.084 30.12 ;
    END
  END o[249]
  PIN o[24]
    DIRECTION OUTPUT ;
    USE SIGNAL ;
    PORT
      LAYER M4 ;
        RECT  0 33.072 0.084 33.096 ;
    END
  END o[24]
  PIN o[250]
    DIRECTION OUTPUT ;
    USE SIGNAL ;
    PORT
      LAYER M4 ;
        RECT  0 30.192 0.084 30.216 ;
    END
  END o[250]
  PIN o[251]
    DIRECTION OUTPUT ;
    USE SIGNAL ;
    PORT
      LAYER M4 ;
        RECT  0 30.288 0.084 30.312 ;
    END
  END o[251]
  PIN o[252]
    DIRECTION OUTPUT ;
    USE SIGNAL ;
    PORT
      LAYER M4 ;
        RECT  0 30.384 0.084 30.408 ;
    END
  END o[252]
  PIN o[253]
    DIRECTION OUTPUT ;
    USE SIGNAL ;
    PORT
      LAYER M4 ;
        RECT  0 30.48 0.084 30.504 ;
    END
  END o[253]
  PIN o[254]
    DIRECTION OUTPUT ;
    USE SIGNAL ;
    PORT
      LAYER M4 ;
        RECT  0 30.576 0.084 30.6 ;
    END
  END o[254]
  PIN o[255]
    DIRECTION OUTPUT ;
    USE SIGNAL ;
    PORT
      LAYER M4 ;
        RECT  0 30.672 0.084 30.696 ;
    END
  END o[255]
  PIN o[256]
    DIRECTION OUTPUT ;
    USE SIGNAL ;
    PORT
      LAYER M4 ;
        RECT  0 15.408 0.084 15.432 ;
    END
  END o[256]
  PIN o[257]
    DIRECTION OUTPUT ;
    USE SIGNAL ;
    PORT
      LAYER M4 ;
        RECT  0 15.504 0.084 15.528 ;
    END
  END o[257]
  PIN o[258]
    DIRECTION OUTPUT ;
    USE SIGNAL ;
    PORT
      LAYER M4 ;
        RECT  0 15.6 0.084 15.624 ;
    END
  END o[258]
  PIN o[259]
    DIRECTION OUTPUT ;
    USE SIGNAL ;
    PORT
      LAYER M4 ;
        RECT  0 15.696 0.084 15.72 ;
    END
  END o[259]
  PIN o[25]
    DIRECTION OUTPUT ;
    USE SIGNAL ;
    PORT
      LAYER M4 ;
        RECT  0 33.168 0.084 33.192 ;
    END
  END o[25]
  PIN o[260]
    DIRECTION OUTPUT ;
    USE SIGNAL ;
    PORT
      LAYER M4 ;
        RECT  0 15.792 0.084 15.816 ;
    END
  END o[260]
  PIN o[261]
    DIRECTION OUTPUT ;
    USE SIGNAL ;
    PORT
      LAYER M4 ;
        RECT  0 15.888 0.084 15.912 ;
    END
  END o[261]
  PIN o[262]
    DIRECTION OUTPUT ;
    USE SIGNAL ;
    PORT
      LAYER M4 ;
        RECT  0 15.984 0.084 16.008 ;
    END
  END o[262]
  PIN o[263]
    DIRECTION OUTPUT ;
    USE SIGNAL ;
    PORT
      LAYER M4 ;
        RECT  0 16.08 0.084 16.104 ;
    END
  END o[263]
  PIN o[264]
    DIRECTION OUTPUT ;
    USE SIGNAL ;
    PORT
      LAYER M4 ;
        RECT  0 16.176 0.084 16.2 ;
    END
  END o[264]
  PIN o[265]
    DIRECTION OUTPUT ;
    USE SIGNAL ;
    PORT
      LAYER M4 ;
        RECT  0 16.272 0.084 16.296 ;
    END
  END o[265]
  PIN o[266]
    DIRECTION OUTPUT ;
    USE SIGNAL ;
    PORT
      LAYER M4 ;
        RECT  0 16.368 0.084 16.392 ;
    END
  END o[266]
  PIN o[267]
    DIRECTION OUTPUT ;
    USE SIGNAL ;
    PORT
      LAYER M4 ;
        RECT  0 16.464 0.084 16.488 ;
    END
  END o[267]
  PIN o[268]
    DIRECTION OUTPUT ;
    USE SIGNAL ;
    PORT
      LAYER M4 ;
        RECT  0 16.56 0.084 16.584 ;
    END
  END o[268]
  PIN o[269]
    DIRECTION OUTPUT ;
    USE SIGNAL ;
    PORT
      LAYER M4 ;
        RECT  0 16.656 0.084 16.68 ;
    END
  END o[269]
  PIN o[26]
    DIRECTION OUTPUT ;
    USE SIGNAL ;
    PORT
      LAYER M4 ;
        RECT  0 33.264 0.084 33.288 ;
    END
  END o[26]
  PIN o[270]
    DIRECTION OUTPUT ;
    USE SIGNAL ;
    PORT
      LAYER M4 ;
        RECT  0 16.752 0.084 16.776 ;
    END
  END o[270]
  PIN o[271]
    DIRECTION OUTPUT ;
    USE SIGNAL ;
    PORT
      LAYER M4 ;
        RECT  0 16.848 0.084 16.872 ;
    END
  END o[271]
  PIN o[272]
    DIRECTION OUTPUT ;
    USE SIGNAL ;
    PORT
      LAYER M4 ;
        RECT  0 16.944 0.084 16.968 ;
    END
  END o[272]
  PIN o[273]
    DIRECTION OUTPUT ;
    USE SIGNAL ;
    PORT
      LAYER M4 ;
        RECT  0 17.04 0.084 17.064 ;
    END
  END o[273]
  PIN o[274]
    DIRECTION OUTPUT ;
    USE SIGNAL ;
    PORT
      LAYER M4 ;
        RECT  0 17.136 0.084 17.16 ;
    END
  END o[274]
  PIN o[275]
    DIRECTION OUTPUT ;
    USE SIGNAL ;
    PORT
      LAYER M4 ;
        RECT  0 17.232 0.084 17.256 ;
    END
  END o[275]
  PIN o[276]
    DIRECTION OUTPUT ;
    USE SIGNAL ;
    PORT
      LAYER M4 ;
        RECT  0 17.328 0.084 17.352 ;
    END
  END o[276]
  PIN o[277]
    DIRECTION OUTPUT ;
    USE SIGNAL ;
    PORT
      LAYER M4 ;
        RECT  0 17.424 0.084 17.448 ;
    END
  END o[277]
  PIN o[278]
    DIRECTION OUTPUT ;
    USE SIGNAL ;
    PORT
      LAYER M4 ;
        RECT  0 17.52 0.084 17.544 ;
    END
  END o[278]
  PIN o[279]
    DIRECTION OUTPUT ;
    USE SIGNAL ;
    PORT
      LAYER M4 ;
        RECT  0 17.616 0.084 17.64 ;
    END
  END o[279]
  PIN o[27]
    DIRECTION OUTPUT ;
    USE SIGNAL ;
    PORT
      LAYER M4 ;
        RECT  0 33.36 0.084 33.384 ;
    END
  END o[27]
  PIN o[280]
    DIRECTION OUTPUT ;
    USE SIGNAL ;
    PORT
      LAYER M4 ;
        RECT  0 17.712 0.084 17.736 ;
    END
  END o[280]
  PIN o[281]
    DIRECTION OUTPUT ;
    USE SIGNAL ;
    PORT
      LAYER M4 ;
        RECT  0 17.808 0.084 17.832 ;
    END
  END o[281]
  PIN o[282]
    DIRECTION OUTPUT ;
    USE SIGNAL ;
    PORT
      LAYER M4 ;
        RECT  0 17.904 0.084 17.928 ;
    END
  END o[282]
  PIN o[283]
    DIRECTION OUTPUT ;
    USE SIGNAL ;
    PORT
      LAYER M4 ;
        RECT  0 18 0.084 18.024 ;
    END
  END o[283]
  PIN o[284]
    DIRECTION OUTPUT ;
    USE SIGNAL ;
    PORT
      LAYER M4 ;
        RECT  0 18.096 0.084 18.12 ;
    END
  END o[284]
  PIN o[285]
    DIRECTION OUTPUT ;
    USE SIGNAL ;
    PORT
      LAYER M4 ;
        RECT  0 18.192 0.084 18.216 ;
    END
  END o[285]
  PIN o[286]
    DIRECTION OUTPUT ;
    USE SIGNAL ;
    PORT
      LAYER M4 ;
        RECT  0 18.288 0.084 18.312 ;
    END
  END o[286]
  PIN o[287]
    DIRECTION OUTPUT ;
    USE SIGNAL ;
    PORT
      LAYER M4 ;
        RECT  0 18.384 0.084 18.408 ;
    END
  END o[287]
  PIN o[288]
    DIRECTION OUTPUT ;
    USE SIGNAL ;
    PORT
      LAYER M4 ;
        RECT  0 13.008 0.084 13.032 ;
    END
  END o[288]
  PIN o[289]
    DIRECTION OUTPUT ;
    USE SIGNAL ;
    PORT
      LAYER M4 ;
        RECT  0 13.104 0.084 13.128 ;
    END
  END o[289]
  PIN o[28]
    DIRECTION OUTPUT ;
    USE SIGNAL ;
    PORT
      LAYER M4 ;
        RECT  0 33.456 0.084 33.48 ;
    END
  END o[28]
  PIN o[290]
    DIRECTION OUTPUT ;
    USE SIGNAL ;
    PORT
      LAYER M4 ;
        RECT  0 13.2 0.084 13.224 ;
    END
  END o[290]
  PIN o[291]
    DIRECTION OUTPUT ;
    USE SIGNAL ;
    PORT
      LAYER M4 ;
        RECT  0 13.296 0.084 13.32 ;
    END
  END o[291]
  PIN o[292]
    DIRECTION OUTPUT ;
    USE SIGNAL ;
    PORT
      LAYER M4 ;
        RECT  0 13.392 0.084 13.416 ;
    END
  END o[292]
  PIN o[293]
    DIRECTION OUTPUT ;
    USE SIGNAL ;
    PORT
      LAYER M4 ;
        RECT  0 13.488 0.084 13.512 ;
    END
  END o[293]
  PIN o[294]
    DIRECTION OUTPUT ;
    USE SIGNAL ;
    PORT
      LAYER M4 ;
        RECT  0 13.584 0.084 13.608 ;
    END
  END o[294]
  PIN o[295]
    DIRECTION OUTPUT ;
    USE SIGNAL ;
    PORT
      LAYER M4 ;
        RECT  0 13.68 0.084 13.704 ;
    END
  END o[295]
  PIN o[296]
    DIRECTION OUTPUT ;
    USE SIGNAL ;
    PORT
      LAYER M4 ;
        RECT  0 13.776 0.084 13.8 ;
    END
  END o[296]
  PIN o[297]
    DIRECTION OUTPUT ;
    USE SIGNAL ;
    PORT
      LAYER M4 ;
        RECT  0 13.872 0.084 13.896 ;
    END
  END o[297]
  PIN o[298]
    DIRECTION OUTPUT ;
    USE SIGNAL ;
    PORT
      LAYER M4 ;
        RECT  0 13.968 0.084 13.992 ;
    END
  END o[298]
  PIN o[299]
    DIRECTION OUTPUT ;
    USE SIGNAL ;
    PORT
      LAYER M4 ;
        RECT  0 14.064 0.084 14.088 ;
    END
  END o[299]
  PIN o[29]
    DIRECTION OUTPUT ;
    USE SIGNAL ;
    PORT
      LAYER M4 ;
        RECT  0 33.552 0.084 33.576 ;
    END
  END o[29]
  PIN o[2]
    DIRECTION OUTPUT ;
    USE SIGNAL ;
    PORT
      LAYER M4 ;
        RECT  0 30.96 0.084 30.984 ;
    END
  END o[2]
  PIN o[300]
    DIRECTION OUTPUT ;
    USE SIGNAL ;
    PORT
      LAYER M4 ;
        RECT  0 14.16 0.084 14.184 ;
    END
  END o[300]
  PIN o[301]
    DIRECTION OUTPUT ;
    USE SIGNAL ;
    PORT
      LAYER M4 ;
        RECT  0 14.256 0.084 14.28 ;
    END
  END o[301]
  PIN o[302]
    DIRECTION OUTPUT ;
    USE SIGNAL ;
    PORT
      LAYER M4 ;
        RECT  0 14.352 0.084 14.376 ;
    END
  END o[302]
  PIN o[303]
    DIRECTION OUTPUT ;
    USE SIGNAL ;
    PORT
      LAYER M4 ;
        RECT  0 14.448 0.084 14.472 ;
    END
  END o[303]
  PIN o[30]
    DIRECTION OUTPUT ;
    USE SIGNAL ;
    PORT
      LAYER M4 ;
        RECT  0 33.648 0.084 33.672 ;
    END
  END o[30]
  PIN o[31]
    DIRECTION OUTPUT ;
    USE SIGNAL ;
    PORT
      LAYER M4 ;
        RECT  0 33.744 0.084 33.768 ;
    END
  END o[31]
  PIN o[32]
    DIRECTION OUTPUT ;
    USE SIGNAL ;
    PORT
      LAYER M4 ;
        RECT  0 24.624 0.084 24.648 ;
    END
  END o[32]
  PIN o[33]
    DIRECTION OUTPUT ;
    USE SIGNAL ;
    PORT
      LAYER M4 ;
        RECT  0 24.72 0.084 24.744 ;
    END
  END o[33]
  PIN o[34]
    DIRECTION OUTPUT ;
    USE SIGNAL ;
    PORT
      LAYER M4 ;
        RECT  0 24.816 0.084 24.84 ;
    END
  END o[34]
  PIN o[35]
    DIRECTION OUTPUT ;
    USE SIGNAL ;
    PORT
      LAYER M4 ;
        RECT  0 24.912 0.084 24.936 ;
    END
  END o[35]
  PIN o[36]
    DIRECTION OUTPUT ;
    USE SIGNAL ;
    PORT
      LAYER M4 ;
        RECT  0 25.008 0.084 25.032 ;
    END
  END o[36]
  PIN o[37]
    DIRECTION OUTPUT ;
    USE SIGNAL ;
    PORT
      LAYER M4 ;
        RECT  0 25.104 0.084 25.128 ;
    END
  END o[37]
  PIN o[38]
    DIRECTION OUTPUT ;
    USE SIGNAL ;
    PORT
      LAYER M4 ;
        RECT  0 25.2 0.084 25.224 ;
    END
  END o[38]
  PIN o[39]
    DIRECTION OUTPUT ;
    USE SIGNAL ;
    PORT
      LAYER M4 ;
        RECT  0 25.296 0.084 25.32 ;
    END
  END o[39]
  PIN o[3]
    DIRECTION OUTPUT ;
    USE SIGNAL ;
    PORT
      LAYER M4 ;
        RECT  0 31.056 0.084 31.08 ;
    END
  END o[3]
  PIN o[40]
    DIRECTION OUTPUT ;
    USE SIGNAL ;
    PORT
      LAYER M4 ;
        RECT  0 25.392 0.084 25.416 ;
    END
  END o[40]
  PIN o[41]
    DIRECTION OUTPUT ;
    USE SIGNAL ;
    PORT
      LAYER M4 ;
        RECT  0 25.488 0.084 25.512 ;
    END
  END o[41]
  PIN o[42]
    DIRECTION OUTPUT ;
    USE SIGNAL ;
    PORT
      LAYER M4 ;
        RECT  0 25.584 0.084 25.608 ;
    END
  END o[42]
  PIN o[43]
    DIRECTION OUTPUT ;
    USE SIGNAL ;
    PORT
      LAYER M4 ;
        RECT  0 25.68 0.084 25.704 ;
    END
  END o[43]
  PIN o[44]
    DIRECTION OUTPUT ;
    USE SIGNAL ;
    PORT
      LAYER M4 ;
        RECT  0 25.776 0.084 25.8 ;
    END
  END o[44]
  PIN o[45]
    DIRECTION OUTPUT ;
    USE SIGNAL ;
    PORT
      LAYER M4 ;
        RECT  0 25.872 0.084 25.896 ;
    END
  END o[45]
  PIN o[46]
    DIRECTION OUTPUT ;
    USE SIGNAL ;
    PORT
      LAYER M4 ;
        RECT  0 25.968 0.084 25.992 ;
    END
  END o[46]
  PIN o[47]
    DIRECTION OUTPUT ;
    USE SIGNAL ;
    PORT
      LAYER M4 ;
        RECT  0 26.064 0.084 26.088 ;
    END
  END o[47]
  PIN o[48]
    DIRECTION OUTPUT ;
    USE SIGNAL ;
    PORT
      LAYER M4 ;
        RECT  0 26.16 0.084 26.184 ;
    END
  END o[48]
  PIN o[49]
    DIRECTION OUTPUT ;
    USE SIGNAL ;
    PORT
      LAYER M4 ;
        RECT  0 26.256 0.084 26.28 ;
    END
  END o[49]
  PIN o[4]
    DIRECTION OUTPUT ;
    USE SIGNAL ;
    PORT
      LAYER M4 ;
        RECT  0 31.152 0.084 31.176 ;
    END
  END o[4]
  PIN o[50]
    DIRECTION OUTPUT ;
    USE SIGNAL ;
    PORT
      LAYER M4 ;
        RECT  0 26.352 0.084 26.376 ;
    END
  END o[50]
  PIN o[51]
    DIRECTION OUTPUT ;
    USE SIGNAL ;
    PORT
      LAYER M4 ;
        RECT  0 26.448 0.084 26.472 ;
    END
  END o[51]
  PIN o[52]
    DIRECTION OUTPUT ;
    USE SIGNAL ;
    PORT
      LAYER M4 ;
        RECT  0 26.544 0.084 26.568 ;
    END
  END o[52]
  PIN o[53]
    DIRECTION OUTPUT ;
    USE SIGNAL ;
    PORT
      LAYER M4 ;
        RECT  0 26.64 0.084 26.664 ;
    END
  END o[53]
  PIN o[54]
    DIRECTION OUTPUT ;
    USE SIGNAL ;
    PORT
      LAYER M4 ;
        RECT  0 26.736 0.084 26.76 ;
    END
  END o[54]
  PIN o[55]
    DIRECTION OUTPUT ;
    USE SIGNAL ;
    PORT
      LAYER M4 ;
        RECT  0 26.832 0.084 26.856 ;
    END
  END o[55]
  PIN o[56]
    DIRECTION OUTPUT ;
    USE SIGNAL ;
    PORT
      LAYER M4 ;
        RECT  0 26.928 0.084 26.952 ;
    END
  END o[56]
  PIN o[57]
    DIRECTION OUTPUT ;
    USE SIGNAL ;
    PORT
      LAYER M4 ;
        RECT  0 27.024 0.084 27.048 ;
    END
  END o[57]
  PIN o[58]
    DIRECTION OUTPUT ;
    USE SIGNAL ;
    PORT
      LAYER M4 ;
        RECT  0 27.12 0.084 27.144 ;
    END
  END o[58]
  PIN o[59]
    DIRECTION OUTPUT ;
    USE SIGNAL ;
    PORT
      LAYER M4 ;
        RECT  0 27.216 0.084 27.24 ;
    END
  END o[59]
  PIN o[5]
    DIRECTION OUTPUT ;
    USE SIGNAL ;
    PORT
      LAYER M4 ;
        RECT  0 31.248 0.084 31.272 ;
    END
  END o[5]
  PIN o[60]
    DIRECTION OUTPUT ;
    USE SIGNAL ;
    PORT
      LAYER M4 ;
        RECT  0 27.312 0.084 27.336 ;
    END
  END o[60]
  PIN o[61]
    DIRECTION OUTPUT ;
    USE SIGNAL ;
    PORT
      LAYER M4 ;
        RECT  0 27.408 0.084 27.432 ;
    END
  END o[61]
  PIN o[62]
    DIRECTION OUTPUT ;
    USE SIGNAL ;
    PORT
      LAYER M4 ;
        RECT  0 27.504 0.084 27.528 ;
    END
  END o[62]
  PIN o[63]
    DIRECTION OUTPUT ;
    USE SIGNAL ;
    PORT
      LAYER M4 ;
        RECT  0 27.6 0.084 27.624 ;
    END
  END o[63]
  PIN o[64]
    DIRECTION OUTPUT ;
    USE SIGNAL ;
    PORT
      LAYER M4 ;
        RECT  0 2.352 0.084 2.376 ;
    END
  END o[64]
  PIN o[65]
    DIRECTION OUTPUT ;
    USE SIGNAL ;
    PORT
      LAYER M4 ;
        RECT  0 2.448 0.084 2.472 ;
    END
  END o[65]
  PIN o[66]
    DIRECTION OUTPUT ;
    USE SIGNAL ;
    PORT
      LAYER M4 ;
        RECT  0 2.544 0.084 2.568 ;
    END
  END o[66]
  PIN o[67]
    DIRECTION OUTPUT ;
    USE SIGNAL ;
    PORT
      LAYER M4 ;
        RECT  0 2.64 0.084 2.664 ;
    END
  END o[67]
  PIN o[68]
    DIRECTION OUTPUT ;
    USE SIGNAL ;
    PORT
      LAYER M4 ;
        RECT  0 2.736 0.084 2.76 ;
    END
  END o[68]
  PIN o[69]
    DIRECTION OUTPUT ;
    USE SIGNAL ;
    PORT
      LAYER M4 ;
        RECT  0 2.832 0.084 2.856 ;
    END
  END o[69]
  PIN o[6]
    DIRECTION OUTPUT ;
    USE SIGNAL ;
    PORT
      LAYER M4 ;
        RECT  0 31.344 0.084 31.368 ;
    END
  END o[6]
  PIN o[70]
    DIRECTION OUTPUT ;
    USE SIGNAL ;
    PORT
      LAYER M4 ;
        RECT  0 2.928 0.084 2.952 ;
    END
  END o[70]
  PIN o[71]
    DIRECTION OUTPUT ;
    USE SIGNAL ;
    PORT
      LAYER M4 ;
        RECT  0 3.024 0.084 3.048 ;
    END
  END o[71]
  PIN o[72]
    DIRECTION OUTPUT ;
    USE SIGNAL ;
    PORT
      LAYER M4 ;
        RECT  0 3.12 0.084 3.144 ;
    END
  END o[72]
  PIN o[73]
    DIRECTION OUTPUT ;
    USE SIGNAL ;
    PORT
      LAYER M4 ;
        RECT  0 3.216 0.084 3.24 ;
    END
  END o[73]
  PIN o[74]
    DIRECTION OUTPUT ;
    USE SIGNAL ;
    PORT
      LAYER M4 ;
        RECT  0 3.312 0.084 3.336 ;
    END
  END o[74]
  PIN o[75]
    DIRECTION OUTPUT ;
    USE SIGNAL ;
    PORT
      LAYER M4 ;
        RECT  0 3.408 0.084 3.432 ;
    END
  END o[75]
  PIN o[76]
    DIRECTION OUTPUT ;
    USE SIGNAL ;
    PORT
      LAYER M4 ;
        RECT  0 3.504 0.084 3.528 ;
    END
  END o[76]
  PIN o[77]
    DIRECTION OUTPUT ;
    USE SIGNAL ;
    PORT
      LAYER M4 ;
        RECT  0 3.6 0.084 3.624 ;
    END
  END o[77]
  PIN o[78]
    DIRECTION OUTPUT ;
    USE SIGNAL ;
    PORT
      LAYER M4 ;
        RECT  0 3.696 0.084 3.72 ;
    END
  END o[78]
  PIN o[79]
    DIRECTION OUTPUT ;
    USE SIGNAL ;
    PORT
      LAYER M4 ;
        RECT  0 3.792 0.084 3.816 ;
    END
  END o[79]
  PIN o[7]
    DIRECTION OUTPUT ;
    USE SIGNAL ;
    PORT
      LAYER M4 ;
        RECT  0 31.44 0.084 31.464 ;
    END
  END o[7]
  PIN o[80]
    DIRECTION OUTPUT ;
    USE SIGNAL ;
    PORT
      LAYER M4 ;
        RECT  0 3.888 0.084 3.912 ;
    END
  END o[80]
  PIN o[81]
    DIRECTION OUTPUT ;
    USE SIGNAL ;
    PORT
      LAYER M4 ;
        RECT  0 3.984 0.084 4.008 ;
    END
  END o[81]
  PIN o[82]
    DIRECTION OUTPUT ;
    USE SIGNAL ;
    PORT
      LAYER M4 ;
        RECT  0 4.08 0.084 4.104 ;
    END
  END o[82]
  PIN o[83]
    DIRECTION OUTPUT ;
    USE SIGNAL ;
    PORT
      LAYER M4 ;
        RECT  0 4.176 0.084 4.2 ;
    END
  END o[83]
  PIN o[84]
    DIRECTION OUTPUT ;
    USE SIGNAL ;
    PORT
      LAYER M4 ;
        RECT  0 4.272 0.084 4.296 ;
    END
  END o[84]
  PIN o[85]
    DIRECTION OUTPUT ;
    USE SIGNAL ;
    PORT
      LAYER M4 ;
        RECT  0 4.368 0.084 4.392 ;
    END
  END o[85]
  PIN o[86]
    DIRECTION OUTPUT ;
    USE SIGNAL ;
    PORT
      LAYER M4 ;
        RECT  0 4.464 0.084 4.488 ;
    END
  END o[86]
  PIN o[87]
    DIRECTION OUTPUT ;
    USE SIGNAL ;
    PORT
      LAYER M4 ;
        RECT  0 4.56 0.084 4.584 ;
    END
  END o[87]
  PIN o[88]
    DIRECTION OUTPUT ;
    USE SIGNAL ;
    PORT
      LAYER M4 ;
        RECT  0 4.656 0.084 4.68 ;
    END
  END o[88]
  PIN o[89]
    DIRECTION OUTPUT ;
    USE SIGNAL ;
    PORT
      LAYER M4 ;
        RECT  0 4.752 0.084 4.776 ;
    END
  END o[89]
  PIN o[8]
    DIRECTION OUTPUT ;
    USE SIGNAL ;
    PORT
      LAYER M4 ;
        RECT  0 31.536 0.084 31.56 ;
    END
  END o[8]
  PIN o[90]
    DIRECTION OUTPUT ;
    USE SIGNAL ;
    PORT
      LAYER M4 ;
        RECT  0 4.848 0.084 4.872 ;
    END
  END o[90]
  PIN o[91]
    DIRECTION OUTPUT ;
    USE SIGNAL ;
    PORT
      LAYER M4 ;
        RECT  0 4.944 0.084 4.968 ;
    END
  END o[91]
  PIN o[92]
    DIRECTION OUTPUT ;
    USE SIGNAL ;
    PORT
      LAYER M4 ;
        RECT  0 5.04 0.084 5.064 ;
    END
  END o[92]
  PIN o[93]
    DIRECTION OUTPUT ;
    USE SIGNAL ;
    PORT
      LAYER M4 ;
        RECT  0 5.136 0.084 5.16 ;
    END
  END o[93]
  PIN o[94]
    DIRECTION OUTPUT ;
    USE SIGNAL ;
    PORT
      LAYER M4 ;
        RECT  0 5.232 0.084 5.256 ;
    END
  END o[94]
  PIN o[95]
    DIRECTION OUTPUT ;
    USE SIGNAL ;
    PORT
      LAYER M4 ;
        RECT  0 5.328 0.084 5.352 ;
    END
  END o[95]
  PIN o[96]
    DIRECTION OUTPUT ;
    USE SIGNAL ;
    PORT
      LAYER M4 ;
        RECT  0 5.424 0.084 5.448 ;
    END
  END o[96]
  PIN o[97]
    DIRECTION OUTPUT ;
    USE SIGNAL ;
    PORT
      LAYER M4 ;
        RECT  0 5.52 0.084 5.544 ;
    END
  END o[97]
  PIN o[98]
    DIRECTION OUTPUT ;
    USE SIGNAL ;
    PORT
      LAYER M4 ;
        RECT  0 5.616 0.084 5.64 ;
    END
  END o[98]
  PIN o[99]
    DIRECTION OUTPUT ;
    USE SIGNAL ;
    PORT
      LAYER M4 ;
        RECT  0 5.712 0.084 5.736 ;
    END
  END o[99]
  PIN o[9]
    DIRECTION OUTPUT ;
    USE SIGNAL ;
    PORT
      LAYER M4 ;
        RECT  0 31.632 0.084 31.656 ;
    END
  END o[9]
  PIN rs
    DIRECTION INPUT ;
    USE SIGNAL ;
    PORT
      LAYER M5 ;
        RECT  13.104 0 13.128 0.084 ;
    END
  END rs
  PIN rso
    DIRECTION OUTPUT ;
    USE SIGNAL ;
    PORT
      LAYER M4 ;
        RECT  0 14.544 0.084 14.568 ;
    END
  END rso
  PIN VDD
    DIRECTION INOUT ;
    USE POWER ;
    PORT
      LAYER M5 ;
        RECT  18.792 2.151 18.912 32.409 ;
        RECT  16.092 2.151 16.212 32.409 ;
        RECT  13.392 2.151 13.512 32.409 ;
        RECT  10.692 2.151 10.812 32.409 ;
        RECT  7.992 2.151 8.112 32.409 ;
        RECT  5.292 2.151 5.412 32.409 ;
        RECT  2.592 2.151 2.712 32.409 ;
    END
  END VDD
  PIN VSS
    DIRECTION INOUT ;
    USE GROUND ;
    PORT
      LAYER M5 ;
        RECT  18.6 2.137 18.72 32.423 ;
        RECT  15.9 2.137 16.02 32.423 ;
        RECT  13.2 2.137 13.32 32.423 ;
        RECT  10.5 2.137 10.62 32.423 ;
        RECT  7.8 2.137 7.92 32.423 ;
        RECT  5.1 2.137 5.22 32.423 ;
        RECT  2.4 2.137 2.52 32.423 ;
    END
  END VSS
  OBS
    LAYER RVTN ;
     RECT  2.16 2.16 19.44 2.295 ;
     RECT  2.16 2.565 19.44 2.835 ;
     RECT  2.16 3.105 19.44 3.375 ;
     RECT  2.16 3.645 19.44 3.915 ;
     RECT  2.16 4.185 19.44 4.455 ;
     RECT  2.16 4.725 19.44 4.995 ;
     RECT  2.16 5.265 19.44 5.535 ;
     RECT  2.16 5.805 19.44 6.075 ;
     RECT  2.16 6.345 19.44 6.615 ;
     RECT  2.16 6.885 19.44 7.155 ;
     RECT  2.16 7.425 19.44 7.695 ;
     RECT  2.16 7.965 19.44 8.235 ;
     RECT  2.16 8.505 19.44 8.775 ;
     RECT  2.16 9.045 19.44 9.315 ;
     RECT  2.16 9.585 19.44 9.855 ;
     RECT  2.16 10.125 19.44 10.395 ;
     RECT  2.16 10.665 19.44 10.935 ;
     RECT  2.16 11.205 19.44 11.475 ;
     RECT  2.16 11.745 19.44 12.015 ;
     RECT  2.16 12.285 19.44 12.555 ;
     RECT  2.16 12.825 19.44 13.095 ;
     RECT  2.16 13.365 19.44 13.635 ;
     RECT  2.16 13.905 19.44 14.175 ;
     RECT  2.16 14.445 19.44 14.715 ;
     RECT  2.16 14.985 19.44 15.255 ;
     RECT  2.16 15.525 19.44 15.795 ;
     RECT  2.16 16.065 19.44 16.335 ;
     RECT  2.16 16.605 19.44 16.875 ;
     RECT  2.16 17.145 19.44 17.415 ;
     RECT  2.16 17.685 19.44 17.955 ;
     RECT  2.16 18.225 19.44 18.495 ;
     RECT  2.16 18.765 19.44 19.035 ;
     RECT  2.16 19.305 19.44 19.575 ;
     RECT  2.16 19.845 19.44 20.115 ;
     RECT  2.16 20.385 19.44 20.655 ;
     RECT  2.16 20.925 19.44 21.195 ;
     RECT  2.16 21.465 19.44 21.735 ;
     RECT  2.16 22.005 19.44 22.275 ;
     RECT  2.16 22.545 19.44 22.815 ;
     RECT  2.16 23.085 19.44 23.355 ;
     RECT  2.16 23.625 19.44 23.895 ;
     RECT  2.16 24.165 19.44 24.435 ;
     RECT  2.16 24.705 19.44 24.975 ;
     RECT  2.16 25.245 19.44 25.515 ;
     RECT  2.16 25.785 19.44 26.055 ;
     RECT  2.16 26.325 19.44 26.595 ;
     RECT  2.16 26.865 19.44 27.135 ;
     RECT  2.16 27.405 19.44 27.675 ;
     RECT  2.16 27.945 19.44 28.215 ;
     RECT  2.16 28.485 19.44 28.755 ;
     RECT  2.16 29.025 19.44 29.295 ;
     RECT  2.16 29.565 19.44 29.835 ;
     RECT  2.16 30.105 19.44 30.375 ;
     RECT  2.16 30.645 19.44 30.915 ;
     RECT  2.16 31.185 19.44 31.455 ;
     RECT  2.16 31.725 19.44 31.995 ;
     RECT  2.16 32.265 19.44 32.4 ;
    LAYER RVTP ;
     RECT  2.16 2.295 19.44 2.565 ;
     RECT  2.16 2.835 19.44 3.105 ;
     RECT  2.16 3.375 19.44 3.645 ;
     RECT  2.16 3.915 19.44 4.185 ;
     RECT  2.16 4.455 19.44 4.725 ;
     RECT  2.16 4.995 19.44 5.265 ;
     RECT  2.16 5.535 19.44 5.805 ;
     RECT  2.16 6.075 19.44 6.345 ;
     RECT  2.16 6.615 19.44 6.885 ;
     RECT  2.16 7.155 19.44 7.425 ;
     RECT  2.16 7.695 19.44 7.965 ;
     RECT  2.16 8.235 19.44 8.505 ;
     RECT  2.16 8.775 19.44 9.045 ;
     RECT  2.16 9.315 19.44 9.585 ;
     RECT  2.16 9.855 19.44 10.125 ;
     RECT  2.16 10.395 19.44 10.665 ;
     RECT  2.16 10.935 19.44 11.205 ;
     RECT  2.16 11.475 19.44 11.745 ;
     RECT  2.16 12.015 19.44 12.285 ;
     RECT  2.16 12.555 19.44 12.825 ;
     RECT  2.16 13.095 19.44 13.365 ;
     RECT  2.16 13.635 19.44 13.905 ;
     RECT  2.16 14.175 19.44 14.445 ;
     RECT  2.16 14.715 19.44 14.985 ;
     RECT  2.16 15.255 19.44 15.525 ;
     RECT  2.16 15.795 19.44 16.065 ;
     RECT  2.16 16.335 19.44 16.605 ;
     RECT  2.16 16.875 19.44 17.145 ;
     RECT  2.16 17.415 19.44 17.685 ;
     RECT  2.16 17.955 19.44 18.225 ;
     RECT  2.16 18.495 19.44 18.765 ;
     RECT  2.16 19.035 19.44 19.305 ;
     RECT  2.16 19.575 19.44 19.845 ;
     RECT  2.16 20.115 19.44 20.385 ;
     RECT  2.16 20.655 19.44 20.925 ;
     RECT  2.16 21.195 19.44 21.465 ;
     RECT  2.16 21.735 19.44 22.005 ;
     RECT  2.16 22.275 19.44 22.545 ;
     RECT  2.16 22.815 19.44 23.085 ;
     RECT  2.16 23.355 19.44 23.625 ;
     RECT  2.16 23.895 19.44 24.165 ;
     RECT  2.16 24.435 19.44 24.705 ;
     RECT  2.16 24.975 19.44 25.245 ;
     RECT  2.16 25.515 19.44 25.785 ;
     RECT  2.16 26.055 19.44 26.325 ;
     RECT  2.16 26.595 19.44 26.865 ;
     RECT  2.16 27.135 19.44 27.405 ;
     RECT  2.16 27.675 19.44 27.945 ;
     RECT  2.16 28.215 19.44 28.485 ;
     RECT  2.16 28.755 19.44 29.025 ;
     RECT  2.16 29.295 19.44 29.565 ;
     RECT  2.16 29.835 19.44 30.105 ;
     RECT  2.16 30.375 19.44 30.645 ;
     RECT  2.16 30.915 19.44 31.185 ;
     RECT  2.16 31.455 19.44 31.725 ;
     RECT  2.16 31.995 19.44 32.265 ;
    LAYER M1 ;
     RECT  2.16 2.151 19.44 32.409 ;
    LAYER M2 ;
     RECT  0.031 28.8 0.067 28.818 ;
     RECT  0.067 28.8 0.103 29.394 ;
     RECT  0.103 3.726 0.139 3.744 ;
     RECT  0.103 13.644 0.139 13.662 ;
     RECT  0.103 16.416 0.139 16.434 ;
     RECT  0.103 17.316 0.139 17.334 ;
     RECT  0.103 18.774 0.139 19.062 ;
     RECT  0.103 20.466 0.139 20.484 ;
     RECT  0.103 27.684 0.139 29.394 ;
     RECT  0.067 32.472 0.139 32.49 ;
     RECT  0.139 32.391 0.167 32.49 ;
     RECT  0.139 3.114 0.175 3.744 ;
     RECT  0.103 12.456 0.175 12.474 ;
     RECT  0.139 13.644 0.175 14.004 ;
     RECT  0.103 15.336 0.175 15.354 ;
     RECT  0.139 18.576 0.175 21.024 ;
     RECT  0.103 22.014 0.175 22.734 ;
     RECT  0.103 24.48 0.175 25.074 ;
     RECT  0.103 11.178 0.203 11.196 ;
     RECT  0.175 13.644 0.211 15.354 ;
     RECT  0.175 24.246 0.211 25.074 ;
     RECT  0.167 32.391 0.239 32.409 ;
     RECT  0.139 27.684 0.247 29.898 ;
     RECT  0.103 30.888 0.247 30.906 ;
     RECT  0.211 24.246 0.283 25.434 ;
     RECT  0.103 26.406 0.283 26.424 ;
     RECT  0.139 16.416 0.391 17.334 ;
     RECT  0.175 18.576 0.391 22.806 ;
     RECT  0.283 24.246 0.391 26.424 ;
     RECT  0.247 27.684 0.391 30.906 ;
     RECT  0.175 12.456 0.427 12.744 ;
     RECT  0.211 13.608 0.427 15.354 ;
     RECT  0.103 6.246 0.463 6.714 ;
     RECT  0.103 7.596 0.463 7.614 ;
     RECT  0.427 12.456 0.463 15.354 ;
     RECT  0.103 5.04 0.499 5.058 ;
     RECT  0.463 6.246 0.499 7.614 ;
     RECT  0.391 16.416 0.499 22.806 ;
     RECT  0.175 3.006 0.535 3.744 ;
     RECT  0.499 5.004 0.535 8.064 ;
     RECT  0.103 8.856 0.535 8.874 ;
     RECT  0.499 16.344 0.535 22.806 ;
     RECT  0.391 24.246 0.535 30.906 ;
     RECT  0.535 32.346 1.147 32.364 ;
     RECT  1.147 32.274 1.175 32.364 ;
     RECT  1.175 32.274 1.615 32.292 ;
     RECT  0.535 24.246 1.651 31.014 ;
     RECT  1.615 32.076 1.651 32.292 ;
     RECT  0.535 2.106 2.16 2.124 ;
     RECT  0.535 3.006 2.16 8.874 ;
     RECT  1.939 10.944 2.16 10.962 ;
     RECT  0.463 12.33 2.16 15.354 ;
     RECT  0.535 16.344 2.16 23.112 ;
     RECT  1.651 24.246 2.16 32.292 ;
     RECT  2.16 2.106 2.767 32.409 ;
     RECT  2.767 2.106 2.983 32.49 ;
     RECT  2.983 1.962 3.271 32.49 ;
     RECT  3.271 1.926 4.991 32.49 ;
     RECT  4.991 1.962 5.531 32.49 ;
     RECT  5.531 2.034 5.999 32.49 ;
     RECT  5.999 2.106 6.323 32.49 ;
     RECT  6.323 2.106 7.087 32.409 ;
     RECT  7.087 2.07 7.951 32.409 ;
     RECT  7.951 2.07 8.923 32.454 ;
     RECT  8.923 1.998 12.191 32.454 ;
     RECT  12.191 1.998 13.667 32.409 ;
     RECT  13.667 2.034 14.827 32.409 ;
     RECT  14.827 1.962 16.051 32.409 ;
     RECT  16.051 1.881 16.591 32.409 ;
     RECT  16.591 1.836 18.455 32.409 ;
     RECT  18.455 1.926 18.959 32.409 ;
     RECT  18.959 1.998 19.44 32.409 ;
     RECT  19.44 1.998 19.715 32.328 ;
     RECT  19.715 1.998 19.823 32.058 ;
     RECT  19.823 2.034 19.895 32.058 ;
     RECT  19.895 2.034 20.111 28.476 ;
     RECT  20.111 14.256 20.399 28.476 ;
     RECT  20.111 2.034 20.435 13.194 ;
     RECT  20.399 14.256 20.435 28.314 ;
     RECT  19.895 29.268 20.435 32.058 ;
     RECT  20.435 2.034 20.507 5.634 ;
     RECT  20.435 6.696 20.507 13.194 ;
     RECT  20.435 17.928 20.507 23.724 ;
     RECT  20.435 24.948 20.507 28.314 ;
     RECT  20.435 29.268 20.507 31.212 ;
     RECT  20.507 6.93 20.543 11.196 ;
     RECT  20.507 12.258 20.543 12.384 ;
     RECT  20.507 20.16 20.543 20.448 ;
     RECT  20.507 22.86 20.543 23.724 ;
     RECT  20.507 25.02 20.543 28.314 ;
     RECT  20.435 14.256 20.579 15.786 ;
     RECT  20.543 28.296 21.307 28.314 ;
     RECT  20.507 29.268 21.307 30.978 ;
     RECT  20.543 6.966 21.343 11.196 ;
     RECT  20.579 14.256 21.371 14.274 ;
     RECT  20.435 31.968 21.371 32.058 ;
     RECT  20.543 12.258 21.379 12.276 ;
     RECT  20.507 2.376 21.407 5.598 ;
     RECT  20.543 25.02 21.407 27.126 ;
     RECT  21.307 28.296 21.407 30.978 ;
     RECT  21.407 3.348 21.443 5.598 ;
     RECT  21.343 6.786 21.443 11.196 ;
     RECT  20.579 15.066 21.443 15.786 ;
     RECT  20.507 19.008 21.443 19.368 ;
     RECT  20.543 20.358 21.443 20.448 ;
     RECT  21.407 26.568 21.443 27.126 ;
     RECT  21.407 28.296 21.443 30.636 ;
     RECT  21.407 2.376 21.479 2.592 ;
     RECT  21.443 3.726 21.479 5.598 ;
     RECT  21.443 6.786 21.479 9.882 ;
     RECT  21.443 10.674 21.479 11.124 ;
     RECT  21.379 12.258 21.479 12.348 ;
     RECT  21.443 19.008 21.479 19.098 ;
     RECT  21.443 20.43 21.479 20.448 ;
     RECT  20.507 21.474 21.479 22.104 ;
     RECT  21.479 2.376 21.515 2.394 ;
     RECT  21.479 3.726 21.515 3.744 ;
     RECT  21.479 4.5 21.515 5.598 ;
     RECT  21.479 6.786 21.515 7.488 ;
     RECT  21.479 8.244 21.515 8.919 ;
     RECT  21.479 9.864 21.515 9.882 ;
     RECT  21.479 10.674 21.515 10.692 ;
     RECT  20.507 13.176 21.515 13.194 ;
     RECT  21.443 15.066 21.515 15.318 ;
     RECT  20.435 16.614 21.515 17.1 ;
     RECT  21.479 19.08 21.515 19.098 ;
     RECT  21.479 21.474 21.515 21.492 ;
     RECT  20.543 23.166 21.515 23.724 ;
     RECT  21.407 25.02 21.515 25.704 ;
     RECT  21.443 28.296 21.515 30.168 ;
     RECT  21.515 25.02 21.551 25.038 ;
     RECT  21.515 29.034 21.551 29.052 ;
     RECT  21.515 8.901 21.587 8.919 ;
     RECT  21.479 12.258 21.587 12.276 ;
     RECT  21.515 23.211 21.587 23.229 ;
     RECT  21.515 29.808 21.587 29.826 ;
     RECT  21.371 31.968 21.587 31.986 ;
    LAYER M3 ;
     RECT  19.404 0.715 19.422 0.907 ;
     RECT  19.368 0.907 19.422 1.003 ;
     RECT  18.288 0.811 18.306 1.099 ;
     RECT  19.368 1.003 19.926 1.195 ;
     RECT  19.368 1.195 20.43 1.387 ;
     RECT  19.368 1.387 20.502 1.483 ;
     RECT  18.144 1.099 18.306 1.675 ;
     RECT  18.108 1.675 18.306 1.831 ;
     RECT  16.596 1.831 16.614 1.876 ;
     RECT  18.108 1.831 18.45 1.921 ;
     RECT  19.224 1.483 20.502 1.921 ;
     RECT  3.276 1.921 3.294 1.957 ;
     RECT  4.968 1.921 4.986 1.957 ;
     RECT  16.056 1.876 16.614 1.957 ;
     RECT  13.14 0.091 13.158 1.993 ;
     RECT  16.056 1.957 17.154 1.993 ;
     RECT  18.108 1.921 20.502 1.993 ;
     RECT  2.988 1.957 3.294 2.029 ;
     RECT  4.968 1.957 5.526 2.029 ;
     RECT  13.14 1.993 13.662 2.029 ;
     RECT  16.056 1.993 20.502 2.029 ;
     RECT  2.988 2.029 3.618 2.101 ;
     RECT  2.7 2.101 3.978 2.143 ;
     RECT  7.092 2.065 7.11 2.143 ;
     RECT  21.492 2.059 21.51 2.155 ;
     RECT  2.415 2.143 3.978 2.191 ;
     RECT  4.968 2.029 5.994 2.191 ;
     RECT  12.924 2.029 13.662 2.191 ;
     RECT  14.832 1.957 14.85 2.191 ;
     RECT  15.588 2.029 20.502 2.191 ;
     RECT  2.415 2.191 5.994 2.263 ;
     RECT  2.415 2.263 6.282 2.299 ;
     RECT  8.928 1.993 8.946 2.299 ;
     RECT  10.515 2.143 10.605 2.299 ;
     RECT  7.092 2.143 7.905 2.335 ;
     RECT  8.928 2.299 9.342 2.335 ;
     RECT  12.924 2.191 13.77 2.335 ;
     RECT  14.832 2.191 20.502 2.335 ;
     RECT  2.415 2.299 6.354 2.371 ;
     RECT  7.092 2.335 9.558 2.371 ;
     RECT  10.515 2.299 10.854 2.371 ;
     RECT  11.988 2.299 12.006 2.371 ;
     RECT  0.54 2.101 0.558 2.381 ;
     RECT  2.34 2.371 12.006 2.443 ;
     RECT  21.456 2.155 21.51 2.443 ;
     RECT  2.304 2.443 12.006 2.461 ;
     RECT  12.78 2.335 13.77 2.461 ;
     RECT  2.304 2.461 13.77 2.533 ;
     RECT  14.508 2.335 20.502 2.533 ;
     RECT  2.304 2.533 20.502 2.597 ;
     RECT  0.324 2.923 0.342 3.001 ;
     RECT  0.18 3.001 0.342 3.109 ;
     RECT  0.144 3.109 0.342 3.145 ;
     RECT  12.42 2.597 20.502 3.173 ;
     RECT  2.304 2.597 11.646 3.208 ;
     RECT  12.42 3.173 20.43 3.209 ;
     RECT  21.42 2.443 21.51 3.211 ;
     RECT  2.268 3.208 11.646 3.299 ;
     RECT  0.144 3.145 0.522 3.379 ;
     RECT  2.304 3.299 11.646 3.451 ;
     RECT  12.42 3.209 20.214 3.451 ;
     RECT  21.384 3.211 21.51 3.499 ;
     RECT  0.144 3.379 0.558 3.721 ;
     RECT  0.108 3.721 0.558 3.725 ;
     RECT  0.108 3.725 0.522 4.205 ;
     RECT  2.304 3.451 20.214 4.363 ;
     RECT  2.304 4.363 20.502 4.523 ;
     RECT  9.504 4.523 20.502 4.541 ;
     RECT  9.504 4.541 10.926 4.829 ;
     RECT  21.312 3.499 21.51 4.829 ;
     RECT  0.54 4.459 0.558 4.999 ;
     RECT  0.504 4.999 0.558 5.035 ;
     RECT  0.108 5.035 0.558 5.131 ;
     RECT  9.504 4.829 10.818 5.189 ;
     RECT  0.108 5.131 1.278 5.261 ;
     RECT  2.304 4.523 8.766 5.305 ;
     RECT  21.348 4.829 21.51 5.369 ;
     RECT  0.108 5.261 1.17 5.453 ;
     RECT  21.384 5.369 21.51 5.603 ;
     RECT  11.772 4.541 20.502 5.707 ;
     RECT  9.972 5.189 10.818 5.773 ;
     RECT  11.592 5.707 20.502 5.773 ;
     RECT  2.304 5.305 9.198 5.971 ;
     RECT  9.972 5.773 20.502 5.971 ;
     RECT  2.304 5.971 20.502 6.029 ;
     RECT  0.108 5.453 0.558 6.619 ;
     RECT  0.108 6.619 1.17 6.719 ;
     RECT  21.384 5.603 21.474 6.763 ;
     RECT  21.384 6.763 21.51 6.781 ;
     RECT  2.376 6.029 20.502 6.893 ;
     RECT  2.376 6.893 19.458 6.925 ;
     RECT  20.196 6.893 20.502 6.925 ;
     RECT  20.196 6.925 20.538 6.989 ;
     RECT  2.34 6.925 19.458 7.051 ;
     RECT  21.348 6.781 21.51 7.159 ;
     RECT  20.196 6.989 20.502 7.187 ;
     RECT  2.304 7.051 19.458 7.223 ;
     RECT  20.232 7.187 20.502 8.141 ;
     RECT  2.304 7.223 19.386 8.203 ;
     RECT  20.232 8.141 20.43 8.203 ;
     RECT  0.108 6.719 0.558 8.621 ;
     RECT  0.108 8.621 0.522 8.717 ;
     RECT  2.304 8.203 20.43 8.843 ;
     RECT  21.24 7.159 21.51 8.896 ;
     RECT  14.76 8.843 20.43 8.971 ;
     RECT  21.24 8.896 21.582 8.971 ;
     RECT  2.304 8.843 13.986 8.977 ;
     RECT  2.268 8.977 13.986 9.149 ;
     RECT  2.268 9.149 13.842 9.197 ;
     RECT  14.76 8.971 21.582 9.275 ;
     RECT  0.108 8.717 0.126 9.293 ;
     RECT  0.144 9.451 0.162 9.499 ;
     RECT  0.144 9.499 0.234 9.677 ;
     RECT  2.304 9.197 13.842 9.923 ;
     RECT  10.404 9.923 13.842 10.021 ;
     RECT  14.832 9.275 21.582 10.021 ;
     RECT  2.304 9.923 9.594 10.027 ;
     RECT  0.144 9.677 0.162 10.253 ;
     RECT  10.404 10.021 21.582 10.463 ;
     RECT  10.404 10.463 20.502 10.589 ;
     RECT  0.324 10.507 0.342 10.637 ;
     RECT  1.944 10.027 9.594 10.651 ;
     RECT  1.944 10.651 9.666 10.769 ;
     RECT  21.24 10.463 21.582 10.829 ;
     RECT  21.276 10.829 21.582 10.931 ;
     RECT  1.944 10.769 9.306 10.967 ;
     RECT  10.404 10.589 13.698 11.011 ;
     RECT  0.108 11.083 0.198 11.201 ;
     RECT  10.08 11.011 13.698 11.201 ;
     RECT  2.232 10.967 9.306 11.309 ;
     RECT  2.268 11.309 9.306 11.399 ;
     RECT  0.144 11.201 0.162 11.405 ;
     RECT  10.26 11.201 13.698 11.419 ;
     RECT  14.436 10.589 20.502 11.419 ;
     RECT  2.268 11.399 8.19 11.507 ;
     RECT  10.26 11.419 20.502 11.543 ;
     RECT  20.196 11.543 20.502 11.579 ;
     RECT  9.036 11.399 9.306 11.669 ;
     RECT  21.384 10.931 21.582 11.851 ;
     RECT  10.26 11.543 19.35 11.939 ;
     RECT  10.26 11.939 13.914 11.975 ;
     RECT  14.724 11.939 19.35 12.209 ;
     RECT  21.348 11.851 21.582 12.281 ;
     RECT  1.152 10.411 1.17 12.325 ;
     RECT  20.196 11.579 20.466 12.325 ;
     RECT  19.98 12.325 20.466 12.361 ;
     RECT  0.468 12.325 1.17 12.451 ;
     RECT  2.304 11.507 8.19 12.559 ;
     RECT  9.036 11.669 9.054 12.559 ;
     RECT  19.98 12.361 20.538 12.619 ;
     RECT  21.348 12.281 21.51 12.619 ;
     RECT  2.304 12.559 9.522 12.631 ;
     RECT  10.26 11.975 13.878 12.631 ;
     RECT  2.304 12.631 13.878 12.715 ;
     RECT  14.724 12.209 19.242 12.715 ;
     RECT  19.98 12.619 21.51 12.845 ;
     RECT  2.304 12.715 19.242 12.865 ;
     RECT  0.108 12.451 1.17 12.929 ;
     RECT  2.088 12.865 19.242 12.955 ;
     RECT  19.98 12.845 20.538 12.955 ;
     RECT  2.088 12.955 20.538 12.974 ;
     RECT  2.232 12.974 20.538 13.091 ;
     RECT  21.348 12.845 21.51 13.199 ;
     RECT  14.796 13.091 20.538 13.613 ;
     RECT  2.232 13.091 13.878 13.739 ;
     RECT  2.268 13.739 13.878 13.819 ;
     RECT  14.796 13.613 20.502 13.819 ;
     RECT  0.108 12.929 0.558 13.901 ;
     RECT  21.348 13.199 21.366 14.279 ;
     RECT  0.144 13.901 0.558 14.381 ;
     RECT  2.268 13.819 20.502 14.573 ;
     RECT  2.304 14.573 20.502 14.719 ;
     RECT  2.304 14.719 20.574 15.149 ;
     RECT  0.144 14.381 0.27 15.259 ;
     RECT  0.144 15.259 0.306 15.331 ;
     RECT  21.492 14.827 21.51 15.403 ;
     RECT  0.108 15.331 0.306 15.437 ;
     RECT  0.144 15.437 0.306 15.533 ;
     RECT  21.42 15.403 21.51 15.533 ;
     RECT  2.304 15.149 20.538 15.821 ;
     RECT  21.42 15.533 21.438 15.979 ;
     RECT  2.304 15.821 20.43 16.133 ;
     RECT  21.312 15.979 21.438 16.267 ;
     RECT  21.312 16.267 21.51 16.301 ;
     RECT  0.18 15.533 0.306 16.339 ;
     RECT  2.304 16.133 19.458 16.397 ;
     RECT  20.196 16.133 20.43 16.403 ;
     RECT  0.18 16.339 0.522 16.411 ;
     RECT  2.304 16.397 19.386 16.501 ;
     RECT  20.52 16.555 20.538 16.681 ;
     RECT  0.108 16.411 0.522 16.771 ;
     RECT  20.52 16.681 20.61 16.781 ;
     RECT  0.108 16.771 1.17 16.979 ;
     RECT  2.268 16.501 19.386 17.021 ;
     RECT  20.52 16.781 20.538 17.069 ;
     RECT  21.42 16.301 21.51 17.117 ;
     RECT  21.492 17.117 21.51 17.165 ;
     RECT  0.108 16.979 0.558 17.261 ;
     RECT  2.304 17.021 19.386 17.323 ;
     RECT  2.304 17.323 20.43 17.447 ;
     RECT  2.304 17.447 19.386 17.519 ;
     RECT  2.304 17.519 19.314 17.549 ;
     RECT  20.412 17.447 20.43 17.899 ;
     RECT  0.108 17.261 0.522 18.031 ;
     RECT  2.34 17.549 19.314 18.283 ;
     RECT  20.412 17.899 20.502 18.283 ;
     RECT  2.34 18.283 20.502 18.491 ;
     RECT  0.108 18.031 0.558 18.509 ;
     RECT  2.34 18.491 20.43 18.535 ;
     RECT  2.304 18.535 20.43 18.599 ;
     RECT  2.304 18.599 19.278 18.689 ;
     RECT  21.492 18.475 21.51 18.763 ;
     RECT  21.456 18.763 21.51 18.955 ;
     RECT  21.42 18.955 21.51 19.103 ;
     RECT  0.108 18.509 0.522 19.339 ;
     RECT  21.42 19.103 21.438 19.373 ;
     RECT  0.108 19.339 1.17 19.565 ;
     RECT  20.196 18.599 20.43 19.615 ;
     RECT  2.304 18.689 19.242 19.627 ;
     RECT  1.152 19.565 1.17 19.915 ;
     RECT  1.98 19.627 19.242 19.915 ;
     RECT  1.152 19.915 19.242 20.083 ;
     RECT  20.196 19.615 20.502 20.083 ;
     RECT  1.152 20.083 20.502 20.155 ;
     RECT  1.152 20.155 20.538 20.237 ;
     RECT  0.108 19.565 0.198 20.353 ;
     RECT  1.152 20.237 19.962 20.353 ;
     RECT  21.42 20.107 21.438 20.425 ;
     RECT  21.42 20.425 21.474 20.587 ;
     RECT  21.312 20.587 21.474 20.683 ;
     RECT  21.312 20.683 21.51 20.717 ;
     RECT  0.108 20.353 19.962 20.813 ;
     RECT  1.152 20.813 19.962 20.971 ;
     RECT  1.152 20.971 20.43 21.067 ;
     RECT  1.152 21.067 20.502 21.299 ;
     RECT  21.456 20.717 21.51 21.497 ;
     RECT  0.108 20.813 0.342 21.541 ;
     RECT  21.456 21.497 21.474 21.547 ;
     RECT  1.728 21.299 20.502 21.703 ;
     RECT  21.42 21.547 21.474 22.001 ;
     RECT  0.108 21.541 0.558 22.061 ;
     RECT  21.456 22.001 21.474 22.109 ;
     RECT  1.728 21.703 20.574 22.253 ;
     RECT  1.728 22.253 20.538 22.379 ;
     RECT  0.108 22.061 0.522 22.829 ;
     RECT  1.98 22.379 20.538 22.919 ;
     RECT  0.144 22.829 0.522 22.925 ;
     RECT  0.18 22.925 0.522 23.089 ;
     RECT  0.18 23.089 0.558 23.117 ;
     RECT  2.304 22.919 20.538 23.117 ;
     RECT  21.492 22.795 21.51 23.206 ;
     RECT  2.304 23.117 20.502 23.351 ;
     RECT  0.54 23.117 0.558 23.405 ;
     RECT  21.492 23.206 21.582 23.467 ;
     RECT  21.42 23.467 21.582 23.621 ;
     RECT  21.456 23.621 21.582 23.693 ;
     RECT  2.304 23.351 20.466 23.701 ;
     RECT  21.492 23.693 21.582 23.729 ;
     RECT  2.268 23.701 20.466 23.789 ;
     RECT  0.18 24.241 0.198 24.331 ;
     RECT  0.18 24.331 0.342 24.46 ;
     RECT  2.304 23.789 20.466 24.523 ;
     RECT  21.564 23.729 21.582 24.619 ;
     RECT  0.108 24.46 0.342 24.709 ;
     RECT  0.108 24.709 0.558 24.955 ;
     RECT  2.304 24.523 20.502 25.195 ;
     RECT  2.304 25.195 20.538 25.387 ;
     RECT  21.492 24.619 21.582 25.963 ;
     RECT  2.304 25.387 20.61 26.087 ;
     RECT  21.384 25.963 21.582 26.321 ;
     RECT  0.036 24.955 0.558 26.941 ;
     RECT  0.036 26.941 1.17 27.059 ;
     RECT  21.42 26.321 21.582 27.131 ;
     RECT  2.304 26.087 20.538 27.499 ;
     RECT  2.268 27.499 20.538 27.707 ;
     RECT  2.268 27.707 20.43 27.977 ;
     RECT  21.492 27.131 21.582 28.171 ;
     RECT  2.304 27.977 20.43 28.555 ;
     RECT  0.036 27.059 0.558 28.823 ;
     RECT  21.456 28.171 21.582 28.939 ;
     RECT  21.42 28.939 21.582 29.029 ;
     RECT  21.312 29.029 21.582 29.323 ;
     RECT  2.304 28.555 20.502 29.633 ;
     RECT  21.276 29.323 21.582 29.831 ;
     RECT  0.072 28.823 0.558 29.911 ;
     RECT  21.276 29.831 21.51 30.371 ;
     RECT  2.376 29.633 20.502 30.415 ;
     RECT  2.34 30.415 20.502 30.451 ;
     RECT  0.072 29.911 0.846 30.649 ;
     RECT  21.348 30.371 21.51 30.667 ;
     RECT  2.304 30.451 20.502 31.109 ;
     RECT  13.104 31.109 20.502 31.145 ;
     RECT  2.304 31.109 12.366 31.181 ;
     RECT  14.904 31.145 20.502 31.217 ;
     RECT  0.072 30.649 1.494 31.261 ;
     RECT  2.304 31.181 12.33 31.261 ;
     RECT  13.104 31.145 13.878 31.379 ;
     RECT  14.904 31.217 20.43 31.379 ;
     RECT  13.215 31.379 13.662 31.523 ;
     RECT  15.876 31.379 20.43 31.523 ;
     RECT  14.904 31.379 14.922 31.559 ;
     RECT  0.072 31.261 12.33 31.685 ;
     RECT  15.876 31.523 20.394 31.721 ;
     RECT  0.072 31.685 12.186 31.919 ;
     RECT  21.348 30.667 21.582 31.991 ;
     RECT  0.072 31.919 11.214 32.063 ;
     RECT  21.348 31.991 21.366 32.063 ;
     RECT  0.072 32.063 8.658 32.099 ;
     RECT  13.215 31.523 13.497 32.147 ;
     RECT  15.915 31.721 16.197 32.147 ;
     RECT  0.072 32.099 6.318 32.189 ;
     RECT  7.092 32.099 8.658 32.189 ;
     RECT  9.756 32.063 11.142 32.189 ;
     RECT  17.46 31.721 19.71 32.189 ;
     RECT  9.756 32.189 10.674 32.225 ;
     RECT  4.248 32.189 5.526 32.237 ;
     RECT  4.248 32.237 5.454 32.261 ;
     RECT  7.704 32.189 8.658 32.261 ;
     RECT  9.756 32.225 10.605 32.261 ;
     RECT  18.615 32.189 19.71 32.261 ;
     RECT  17.46 32.189 17.622 32.297 ;
     RECT  4.248 32.261 5.346 32.333 ;
     RECT  7.815 32.261 8.658 32.333 ;
     RECT  19.692 32.261 19.71 32.333 ;
     RECT  10.368 32.261 10.605 32.369 ;
     RECT  17.604 32.297 17.622 32.369 ;
     RECT  7.815 32.333 7.974 32.417 ;
     RECT  10.515 32.369 10.605 32.417 ;
     RECT  13.215 32.147 13.305 32.417 ;
     RECT  15.915 32.147 16.005 32.417 ;
     RECT  18.615 32.261 18.705 32.417 ;
     RECT  0.072 32.189 3.438 32.459 ;
     RECT  4.68 32.333 5.346 32.459 ;
     RECT  7.956 32.417 7.974 32.459 ;
     RECT  12.168 31.919 12.186 32.459 ;
     RECT  0.072 32.459 3.042 32.495 ;
     RECT  6.3 32.189 6.318 32.495 ;
     RECT  0.144 32.495 3.042 32.525 ;
     RECT  0.216 32.525 3.042 32.621 ;
     RECT  4.68 32.459 4.698 32.717 ;
     RECT  0.216 32.621 0.558 32.813 ;
     RECT  0.216 32.813 0.234 33.005 ;
     RECT  1.404 32.621 3.042 33.197 ;
     RECT  1.404 33.197 2.574 33.389 ;
     RECT  1.476 33.389 2.574 33.485 ;
     RECT  1.62 33.485 2.574 33.581 ;
     RECT  2.304 33.581 2.574 33.677 ;
     RECT  2.304 33.677 2.322 33.773 ;
    LAYER M4 ;
     RECT  0.025 24.96 0.06 24.984 ;
     RECT  0.06 13.008 0.173 33.768 ;
     RECT  0.06 2.352 0.569 11.496 ;
     RECT  0.173 13.008 0.569 14.568 ;
     RECT  0.569 2.448 2.293 11.496 ;
     RECT  0.569 13.2 2.329 14.568 ;
     RECT  0.173 15.552 2.329 33.768 ;
     RECT  2.329 13.2 2.333 33.768 ;
     RECT  2.293 2.448 2.408 12.072 ;
     RECT  2.333 13.2 2.408 33.672 ;
     RECT  2.408 2.148 2.512 33.672 ;
     RECT  2.512 2.304 2.585 33.672 ;
     RECT  2.585 2.304 3.053 33.192 ;
     RECT  3.053 2.304 3.413 32.712 ;
     RECT  3.413 2.304 3.449 3.144 ;
     RECT  3.413 4.128 3.449 32.712 ;
     RECT  3.449 17.424 3.485 32.712 ;
     RECT  3.449 2.496 3.521 3.144 ;
     RECT  3.449 4.128 3.521 16.392 ;
     RECT  3.521 2.496 3.593 3.096 ;
     RECT  3.521 4.368 3.737 16.392 ;
     RECT  3.737 4.368 4.097 12.024 ;
     RECT  3.485 18 4.669 32.712 ;
     RECT  4.669 17.616 4.709 32.712 ;
     RECT  3.737 13.104 4.813 16.392 ;
     RECT  4.813 13.056 5.029 16.392 ;
     RECT  3.593 2.832 5.108 3.096 ;
     RECT  4.097 4.368 5.108 6.264 ;
     RECT  4.097 7.344 5.108 12.024 ;
     RECT  5.029 13.056 5.108 16.632 ;
     RECT  4.709 17.616 5.108 32.412 ;
     RECT  5.108 2.148 5.212 32.412 ;
     RECT  5.212 2.304 5.404 32.28 ;
     RECT  5.404 2.304 6.365 18.264 ;
     RECT  5.404 19.584 6.541 32.28 ;
     RECT  6.365 2.448 6.793 18.264 ;
     RECT  6.541 19.536 6.793 32.28 ;
     RECT  6.793 2.448 7.808 32.28 ;
     RECT  7.808 2.148 7.912 32.412 ;
     RECT  7.912 2.352 8.093 32.28 ;
     RECT  8.093 2.352 8.104 32.142 ;
     RECT  8.104 2.352 8.417 11.256 ;
     RECT  8.417 2.352 8.849 11.208 ;
     RECT  8.849 2.496 9.461 11.208 ;
     RECT  9.461 2.544 10.508 11.208 ;
     RECT  8.104 12.576 10.508 32.088 ;
     RECT  10.508 2.148 10.612 32.412 ;
     RECT  10.612 2.418 10.804 32.142 ;
     RECT  10.804 2.544 10.931 31.944 ;
     RECT  10.931 2.544 11.699 30.408 ;
     RECT  11.699 12.432 12.409 30.408 ;
     RECT  12.409 12.432 12.445 30.456 ;
     RECT  12.445 12.432 12.517 30.6 ;
     RECT  11.699 2.544 12.769 11.208 ;
     RECT  12.517 12.432 13.021 30.648 ;
     RECT  13.085 0.096 13.169 0.12 ;
     RECT  12.769 2.496 13.208 11.208 ;
     RECT  13.021 12.432 13.208 30.936 ;
     RECT  13.208 2.148 13.312 32.412 ;
     RECT  13.312 2.418 13.504 32.142 ;
     RECT  13.504 12.48 14.291 30.936 ;
     RECT  14.291 12.48 14.393 28.488 ;
     RECT  14.291 29.52 14.753 30.936 ;
     RECT  14.753 29.76 14.965 30.936 ;
     RECT  13.504 2.448 15.037 11.448 ;
     RECT  14.393 12.48 15.037 22.776 ;
     RECT  14.965 29.76 15.145 30.984 ;
     RECT  14.393 24.096 15.505 28.488 ;
     RECT  15.037 2.448 15.613 22.776 ;
     RECT  15.505 23.952 15.613 28.488 ;
     RECT  15.613 2.448 15.908 28.488 ;
     RECT  15.145 29.76 15.908 31.176 ;
     RECT  15.908 2.148 16.012 32.412 ;
     RECT  16.012 2.418 16.204 32.142 ;
     RECT  16.204 2.418 16.337 31.368 ;
     RECT  16.337 2.418 17.053 30.168 ;
     RECT  16.337 31.344 17.129 31.368 ;
     RECT  17.053 2.208 17.521 30.168 ;
     RECT  17.521 2.208 18.097 30.84 ;
     RECT  18.097 1.68 18.1 30.84 ;
     RECT  18.1 1.68 18.133 30.888 ;
     RECT  18.133 1.104 18.169 30.888 ;
     RECT  18.169 1.104 18.277 31.8 ;
     RECT  18.277 0.816 18.608 31.8 ;
     RECT  18.608 0.816 18.712 32.412 ;
     RECT  18.712 0.816 18.904 32.142 ;
     RECT  18.904 9.072 19.037 31.8 ;
     RECT  19.037 9.072 19.109 31.464 ;
     RECT  19.109 31.44 19.145 31.464 ;
     RECT  18.904 0.816 19.393 8.04 ;
     RECT  19.393 0.72 19.897 8.04 ;
     RECT  19.109 9.072 19.897 30.216 ;
     RECT  19.897 0.72 20.365 30.216 ;
     RECT  20.365 0.72 21.481 30.6 ;
     RECT  21.481 0.72 21.564 30.696 ;
     RECT  21.564 30.672 21.593 30.696 ;
    LAYER M5 ;
     RECT  13.008 0.016 13.128 0.131 ;
     RECT  13.008 0.131 13.032 2.137 ;
     RECT  2.4 2.137 2.52 2.151 ;
     RECT  5.1 2.137 5.22 2.151 ;
     RECT  7.8 2.137 7.92 2.151 ;
     RECT  10.5 2.137 10.62 2.151 ;
     RECT  13.008 2.137 13.32 2.151 ;
     RECT  15.9 2.137 16.02 2.151 ;
     RECT  18.6 2.137 18.72 2.151 ;
     RECT  15.9 2.151 16.212 2.725 ;
     RECT  13.008 2.151 13.512 2.773 ;
     RECT  5.1 2.151 5.412 2.821 ;
     RECT  18.6 2.151 18.912 2.821 ;
     RECT  0.144 2.869 0.168 3.059 ;
     RECT  15.024 2.725 16.212 3.157 ;
     RECT  13.008 2.773 13.656 3.923 ;
     RECT  10.5 2.151 10.812 3.925 ;
     RECT  15.024 3.157 16.536 4.067 ;
     RECT  5.1 2.821 6.12 4.115 ;
     RECT  7.8 2.151 8.112 4.117 ;
     RECT  15.9 4.067 16.536 4.789 ;
     RECT  18.48 2.821 18.912 4.933 ;
     RECT  10.5 3.925 11.592 5.461 ;
     RECT  13.008 3.923 13.512 5.557 ;
     RECT  5.1 4.115 5.412 5.605 ;
     RECT  18.192 4.933 18.912 5.795 ;
     RECT  15.9 4.789 16.632 5.891 ;
     RECT  10.5 5.461 11.88 6.277 ;
     RECT  13.008 5.557 13.656 6.277 ;
     RECT  7.8 4.117 9.096 6.563 ;
     RECT  10.5 6.277 13.656 6.611 ;
     RECT  10.5 6.611 10.812 6.805 ;
     RECT  11.856 6.611 13.656 6.805 ;
     RECT  15.9 5.891 16.344 6.899 ;
     RECT  18.48 5.795 18.912 6.899 ;
     RECT  7.8 6.563 8.112 7.333 ;
     RECT  11.856 6.805 14.424 7.427 ;
     RECT  5.1 5.605 6.312 7.765 ;
     RECT  7.68 7.333 8.112 7.765 ;
     RECT  15.9 6.899 16.212 8.197 ;
     RECT  17.232 7.093 17.256 8.197 ;
     RECT  9.36 6.805 10.812 8.483 ;
     RECT  11.856 7.427 13.512 8.483 ;
     RECT  9.36 8.483 9.384 8.819 ;
     RECT  5.1 7.765 8.112 9.011 ;
     RECT  21.408 9.877 21.432 10.163 ;
     RECT  15.9 8.197 17.256 10.213 ;
     RECT  2.4 2.151 2.712 10.405 ;
     RECT  0.144 10.357 0.168 10.643 ;
     RECT  15.9 10.213 17.448 10.693 ;
     RECT  18.6 6.899 18.912 10.693 ;
     RECT  10.5 8.483 10.812 10.789 ;
     RECT  11.856 8.483 11.88 10.789 ;
     RECT  6.528 9.011 8.112 11.459 ;
     RECT  15.9 10.693 18.912 11.555 ;
     RECT  17.232 11.555 18.912 11.557 ;
     RECT  2.304 10.405 2.712 12.083 ;
     RECT  5.1 9.011 5.412 12.325 ;
     RECT  10.5 10.789 11.88 12.805 ;
     RECT  15.9 11.555 16.212 12.805 ;
     RECT  17.232 11.557 19.368 12.805 ;
     RECT  15.9 12.805 19.368 12.901 ;
     RECT  10.5 12.805 11.976 13.331 ;
     RECT  11.952 13.331 11.976 13.621 ;
     RECT  13.008 8.483 13.512 13.621 ;
     RECT  15.648 12.901 19.368 13.669 ;
     RECT  5.1 12.325 5.544 13.715 ;
     RECT  11.952 13.621 13.512 13.715 ;
     RECT  14.832 13.669 19.368 13.907 ;
     RECT  7.8 11.459 8.112 14.149 ;
     RECT  15.648 13.907 19.368 14.243 ;
     RECT  6.528 11.459 6.552 14.291 ;
     RECT  12.48 13.715 13.512 14.485 ;
     RECT  15.9 14.243 19.368 14.867 ;
     RECT  12.48 14.485 14.232 14.963 ;
     RECT  15.9 14.867 19.224 15.347 ;
     RECT  12.48 14.963 13.608 15.781 ;
     RECT  5.1 13.715 5.412 15.877 ;
     RECT  7.8 14.149 9.096 16.069 ;
     RECT  7.8 16.069 9.144 16.165 ;
     RECT  7.008 16.165 9.144 16.211 ;
     RECT  15.9 15.347 18.912 16.357 ;
     RECT  7.008 16.211 9.096 16.403 ;
     RECT  5.1 15.877 5.544 16.835 ;
     RECT  0.144 16.597 0.168 16.883 ;
     RECT  15.9 16.357 19.128 16.933 ;
     RECT  15.504 16.933 19.128 17.029 ;
     RECT  7.44 16.403 9.096 17.411 ;
     RECT  12 15.781 13.608 17.459 ;
     RECT  15.504 17.029 19.176 17.555 ;
     RECT  10.5 13.331 10.968 17.605 ;
     RECT  15.504 17.555 18.912 17.749 ;
     RECT  12.528 17.459 13.608 17.845 ;
     RECT  14.784 17.749 18.912 17.845 ;
     RECT  7.44 17.411 8.856 18.467 ;
     RECT  10.5 17.605 11.208 18.565 ;
     RECT  12.528 17.845 18.912 18.661 ;
     RECT  7.8 18.467 8.856 18.757 ;
     RECT  10.5 18.565 11.304 18.995 ;
     RECT  12.528 18.661 19.368 19.427 ;
     RECT  12.528 19.427 18.912 19.523 ;
     RECT  12.528 19.523 13.704 19.619 ;
     RECT  7.8 18.757 9.192 20.579 ;
     RECT  14.832 19.523 18.912 20.579 ;
     RECT  15.9 20.579 18.912 20.965 ;
     RECT  10.5 18.995 11.208 21.205 ;
     RECT  7.8 20.579 8.568 21.445 ;
     RECT  10.5 21.205 11.928 22.019 ;
     RECT  14.832 20.579 14.856 22.019 ;
     RECT  10.5 22.019 11.208 22.259 ;
     RECT  10.5 22.259 10.968 22.309 ;
     RECT  10.272 22.309 10.968 22.355 ;
     RECT  13.2 19.619 13.704 22.453 ;
     RECT  7.68 21.445 8.568 22.549 ;
     RECT  2.4 12.083 2.712 22.837 ;
     RECT  13.2 22.453 14.232 23.411 ;
     RECT  2.4 22.837 2.856 23.555 ;
     RECT  7.68 22.549 9.096 23.555 ;
     RECT  7.8 23.555 9.096 23.557 ;
     RECT  10.272 22.355 10.92 23.557 ;
     RECT  13.2 23.411 13.512 23.557 ;
     RECT  7.8 23.557 10.92 23.699 ;
     RECT  10.5 23.699 10.92 23.939 ;
     RECT  0.144 24.181 0.168 24.467 ;
     RECT  2.4 23.555 2.808 24.467 ;
     RECT  12.24 23.557 13.512 24.515 ;
     RECT  10.5 23.939 10.812 24.949 ;
     RECT  7.8 23.699 9.096 25.045 ;
     RECT  7.152 25.045 9.096 25.091 ;
     RECT  15.9 20.965 19.08 25.139 ;
     RECT  15.9 25.139 16.212 25.237 ;
     RECT  15.072 25.237 16.212 25.379 ;
     RECT  12.528 24.515 13.512 26.101 ;
     RECT  12.528 26.101 13.608 26.243 ;
     RECT  7.152 25.091 8.112 26.771 ;
     RECT  7.8 26.771 8.112 26.773 ;
     RECT  15.9 25.379 16.212 27.205 ;
     RECT  7.8 26.773 8.232 27.445 ;
     RECT  13.104 26.243 13.608 27.445 ;
     RECT  12.192 27.445 13.608 27.683 ;
     RECT  7.8 27.445 9.096 27.827 ;
     RECT  10.368 24.949 10.812 27.829 ;
     RECT  13.104 27.683 13.608 27.923 ;
     RECT  13.2 27.923 13.608 28.405 ;
     RECT  10.368 27.829 10.92 28.453 ;
     RECT  17.664 25.139 19.08 28.547 ;
     RECT  15.9 27.205 16.536 28.789 ;
     RECT  10.272 28.453 10.92 29.173 ;
     RECT  10.176 29.173 10.92 29.315 ;
     RECT  7.8 27.827 8.112 29.605 ;
     RECT  17.664 28.547 19.032 29.699 ;
     RECT  7.44 29.605 8.112 29.891 ;
     RECT  7.8 29.891 8.112 29.893 ;
     RECT  7.8 29.893 8.904 30.373 ;
     RECT  7.8 30.373 9.336 30.515 ;
     RECT  17.664 29.699 18.912 30.851 ;
     RECT  18.144 30.851 18.912 30.899 ;
     RECT  13.2 28.405 14.28 30.947 ;
     RECT  15.9 28.789 16.584 31.379 ;
     RECT  18.24 30.899 18.912 31.379 ;
     RECT  10.5 29.315 10.92 31.955 ;
     RECT  7.8 30.515 8.712 32.099 ;
     RECT  2.4 24.467 2.712 32.409 ;
     RECT  5.1 16.835 5.412 32.409 ;
     RECT  7.8 32.099 8.112 32.409 ;
     RECT  10.5 31.955 10.812 32.409 ;
     RECT  13.2 30.947 13.512 32.409 ;
     RECT  15.9 31.379 16.212 32.409 ;
     RECT  18.6 31.379 18.912 32.409 ;
     RECT  2.4 32.409 2.52 32.423 ;
     RECT  5.1 32.409 5.22 32.423 ;
     RECT  7.8 32.409 7.92 32.423 ;
     RECT  10.5 32.409 10.62 32.423 ;
     RECT  13.2 32.409 13.32 32.423 ;
     RECT  15.9 32.409 16.02 32.423 ;
     RECT  18.6 32.409 18.72 32.423 ;
  END
END hbfd_rly_304_EW_rr
END LIBRARY
